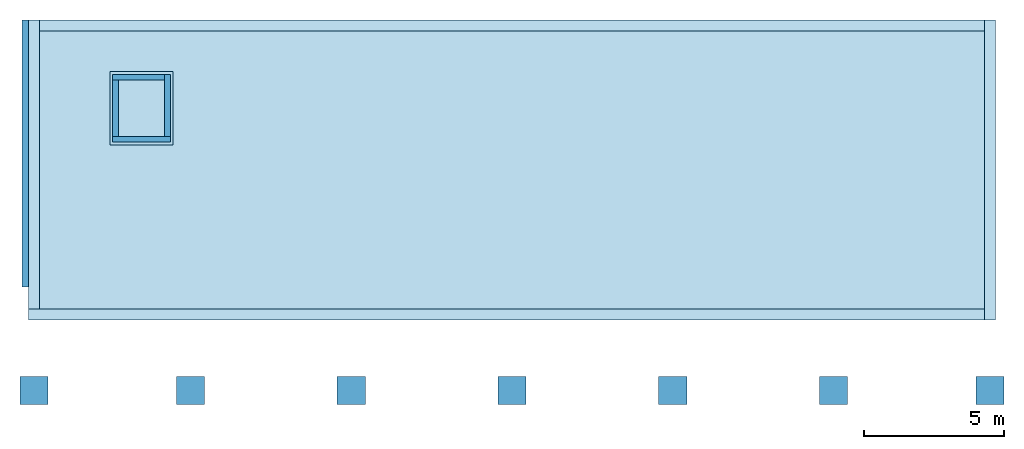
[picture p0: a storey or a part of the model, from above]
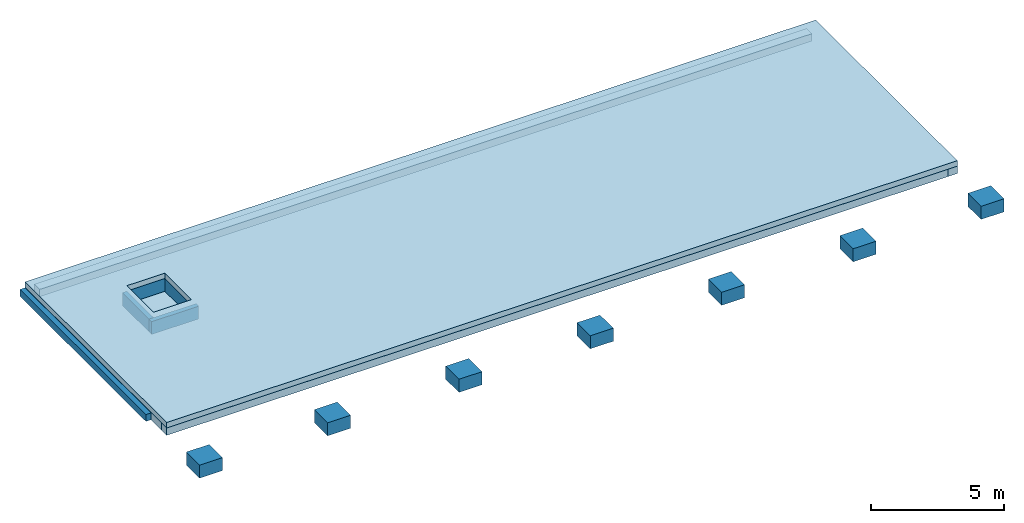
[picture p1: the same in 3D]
Properties of the parts of a building model (IFC4), part 1 of 2

# File
Description: no view
File name: LYC-1518-MDL-DMC-STR-Global.ifc
Time: 2025-12-04T12:50:37
Author: Thibaut
Organization: Adem, bureau d'études, Place de Flandre, 9 - B-7000 Mons
Written by: EDMsix Version 2.0.209.92 Dec 12 2020
Made in: Allplan 2022.1 20.06.2024 - 13:41:00

# IfcSite, Site
RefLatitude: 48, 8, 10, 320000; RefLongitude: 11, 41, 19, 320000

# IfcBuildingStorey (10)
Name | In | Elevation (m)
-01-Fondations | Admin | -0.8
00-Rez | Admin | -0.26
01-Etage1 | Admin | 3.25
02-Etage2 | Admin | 6.61
03-Toiture | Admin | 9.64
-01-Fondations | Auditorium | -0.8
00-Rez | Auditorium | -0.26
01-Toiture | Auditorium | 3.9
-01-Fondations | PosteGarde | -0.02
00-Rez | PosteGarde | 0.88

# IfcSpace (5)
In: 03-Toiture
LongName: Atelier; Classification: 1020 Project Program (Uniformat)
Pset_SpaceCommon - IsExternal: no; HandicapAccessible: yes; GrossPlannedArea: 0 m2; NetPlannedArea: 100 m2; PubliclyAccessible: yes; Reference: AT
Qto_SpaceBaseQuantities - FinishFloorHeight: 0 m
Name | NetFloorArea (m2) | GrossFloorArea (m2) | GrossWallArea (m2) | NetWallArea (m2) | NetPerimeter (m) | GrossVolume (m3) = NetVolume (m3) | FinishCeilingHeight (m)
AT-xx-01 | 17.432 | 17.432 | 4.61 | 1.709 | 18.675 | 4.303 | 0.247
AT-xx-01 | 20.869 | 20.869 | 4.738 | 1.119 | 18.65 | 5.302 | 0.254
2 x AT-xx-01 | 10.202 | 10.202 | 3.285 | 0.547 | 12.93 | 2.592 | 0.254
AT-xx-01 | 0.22 | 294.621 | 43.025 | 29.085 | 152.225 | 83.272 | 0.283

# IfcBeam (143)
Name | In | Classification | Material | Status | LoadBearing | Height (m) | Width (m) | CrossSectionArea (m2) | GrossVolume (m3) | Length (m) | IsExternal | NetVolume (m3) | OuterSurfaceArea (m2)
Linteau préfab. | 00-Rez | B1010 Floor Construction (Uniformat) | C30/37 | NEW | yes | 0.2 | 0.15 | 0.03 | 0.039 | 1.31
PBAr.0.04 | 00-Rez | B2080 Exterior Wall Appurtenances (Uniformat) | Béton architectonique | NEW | no | 1.6 | 0.12 | 0.192 | 6.874 | 35.8 | yes | 6.874 | 123.536
PBAr.0.02 | 00-Rez | B2080 Exterior Wall Appurtenances (Uniformat) | Béton architectonique | NEW | yes | 1.6 | 0.12 | 0.192 | 7.21 | 37.55 | yes | 7.21 | 129.78
PBAr.0.01 | 00-Rez | B2080 Exterior Wall Appurtenances (Uniformat) | Béton architectonique | NEW | yes | 1.6 | 0.12 | 0.192 | 0.691 | 3.6 | yes | 0.691 | 12.768
PBAr.0.03 | 00-Rez | B2080 Exterior Wall Appurtenances (Uniformat) | Béton architectonique | NEW | yes | 1.6 | 0.12 | 0.192 | 2.717 | 14.15 | yes | 2.717 | 49.06
PBA.0.02 | 00-Rez | B1010 Floor Construction (Uniformat) | C30/37 | NEW | yes | 0.07 | 0.16 | 0.011 | 0.013 | 1.13 | yes | 0.013 | 0.542
2 x PBA.0.02 | 00-Rez | B1010 Floor Construction (Uniformat) | C30/37 | NEW | yes | 0.07 | 0.16 | 0.011 | 0.014 | 1.28 | yes | 0.014 | 0.611
PBA.0.02 | 00-Rez | B1010 Floor Construction (Uniformat) | C30/37 | NEW | yes | 1.12 | 0.16 | 0.179 | 1.335 | 7.45 | yes | 1.335 | 19.43
PBA.0.02 | 00-Rez | B1010 Floor Construction (Uniformat) | C30/37 | NEW | yes | 1.12 | 0.16 | 0.179 | 1.821 | 10.16 | yes | 1.821 | 26.368
PBA.0.02 | 00-Rez | B1010 Floor Construction (Uniformat) | C30/37 | NEW | yes | 1.12 | 0.16 | 0.179 | 0.803 | 4.48 | yes | 0.803 | 11.827
PBA.0.02 | 00-Rez | B1010 Floor Construction (Uniformat) | C30/37 | NEW | yes | 1.12 | 0.16 | 0.179 | 0.493 | 2.75 | yes | 0.493 | 7.398
PBA.0.02 | 00-Rez | B1010 Floor Construction (Uniformat) | C30/37 | NEW | yes | 0.07 | 0.16 | 0.011 | 0.014 | 1.24 | yes | 0.014 | 0.593
PBA.0.03 | 00-Rez | B1010 Floor Construction (Uniformat) | C30/37 | NEW | yes | 0.07 | 0.16 | 0.011 | 0.014 | 1.265 | yes | 0.014 | 0.604
PBA.0.03 | 00-Rez | B1010 Floor Construction (Uniformat) | C30/37 | NEW | yes | 1.12 | 0.16 | 0.179 | 0.186 | 1.04 | yes | 0.186 | 3.021
PBA.0.02 | 00-Rez | B1010 Floor Construction (Uniformat) | C30/37 | NEW | yes | 1.12 | 0.16 | 0.179 | 0.74 | 4.13 | yes | 0.74 | 10.931
PBA.0.03 | 00-Rez | B1010 Floor Construction (Uniformat) | C30/37 | NEW | yes | 1.12 | 0.16 | 0.179 | 1.436 | 8.015 | yes | 1.436 | 20.877
PBA.0.02 | 00-Rez | B1010 Floor Construction (Uniformat) | C30/37 | NEW | yes | 0.6 | 0.2 | 0.12 | 4.058 | 33.82 | yes | 4.058 | 54.352
PBA.0.03 | 00-Rez | B1010 Floor Construction (Uniformat) | C30/37 | NEW | yes | 0.6 | 0.2 | 0.12 | 1.234 | 10.28 | yes | 1.234 | 16.688
PBA.0.06 | 00-Rez | B1010 Floor Construction (Uniformat) | C30/37 | NEW | yes | 0.95 | 0.2 | 0.19 | 0.314 | 1.65 | yes | 0.314 | 4.175
PBA.0.07 | 00-Rez | B1010 Floor Construction (Uniformat) | C30/37 | NEW | yes | 0.2 | 0.15 | 0.03 | 0.104 | 3.466 | yes | 0.104 | 2.486
PBA.0.09 | 00-Rez | B1010 Floor Construction (Uniformat) | C30/37 | NEW | yes | 0.08 | 0.214 | 0.017 | 0.055 | 3.22 | yes | 0.055 | 1.928
PBA.0.11 | 00-Rez | B1010 Floor Construction (Uniformat) | C30/37 | NEW | yes | 0.08 | 0.15 | 0.012 | 0.028 | 2.319 | yes | 0.028 | 1.091
PBA.0.10 | 00-Rez | B1010 Floor Construction (Uniformat) | C30/37 | NEW | yes | 0.08 | 0.15 | 0.012 | 0.028 | 2.32 | yes | 0.028 | 1.091
PBA.0.08 | 00-Rez | B1010 Floor Construction (Uniformat) | C30/37 | NEW | yes | 0.08 | 0.214 | 0.017 | 0.024 | 1.4 | yes | 0.024 | 0.857
PBA.0.12 | 00-Rez | B1010 Floor Construction (Uniformat) | C30/37 | NEW | yes | 0.64 | 0.2 | 0.128 | 0.471 | 3.68 | yes | 0.471 | 6.438
PBA.0.01 | 00-Rez | B1010 Floor Construction (Uniformat) | C30/37 | NEW | yes | 1.12 | 0.16 | 0.179 | 0.846 | 4.72 | yes | 0.846 | 12.442
PBA.0.01 | 00-Rez | B1010 Floor Construction (Uniformat) | C30/37 | NEW | yes | 0.6 | 0.2 | 0.12 | 0.566 | 4.72 | yes | 0.566 | 7.792
PBA.0.04 | 00-Rez | B1010 Floor Construction (Uniformat) | C30/37 | NEW | yes | 1.12 | 0.16 | 0.179 | 1.254 | 7 | yes | 1.254 | 18.278
PBA.0.04 | 00-Rez | B1010 Floor Construction (Uniformat) | C30/37 | NEW | yes | 0.6 | 0.2 | 0.12 | 0.84 | 7 | yes | 0.84 | 11.44
PBA.0.05 | 00-Rez | B1010 Floor Construction (Uniformat) | C30/37 | NEW | yes | 0.6 | 0.2 | 0.12 | 1.526 | 12.72 | yes | 1.526 | 20.592
PBA.0.05 | 00-Rez | B1010 Floor Construction (Uniformat) | C30/37 | NEW | yes | 1.12 | 0.16 | 0.179 | 2.279 | 12.72 | yes | 2.279 | 32.922
P 1.05 | 01-Etage1 | B1010 Floor Construction (Uniformat) | GL24h | NEW | yes | 0.52 | 0.2 | 0.104 | 0.477 | 4.59 | yes | 0.477 | 6.818
P 1.04 | 01-Etage1 | B1010 Floor Construction (Uniformat) | GL24h | NEW | yes | 0.52 | 0.2 | 0.104 | 0.477 | 4.59 | yes | 0.477 | 6.818
P 1.03 | 01-Etage1 | B1010 Floor Construction (Uniformat) | GL24h | NEW | yes | 0.52 | 0.2 | 0.104 | 0.477 | 4.59 | yes | 0.477 | 6.818
P 1.14 | 01-Etage1 | B1010 Floor Construction (Uniformat) | GL24h | NEW | yes | 0.4 | 0.2 | 0.08 | 0.262 | 3.27 | yes | 0.262 | 4.084
P 1.13 | 01-Etage1 | B1010 Floor Construction (Uniformat) | GL24h | NEW | yes | 0.4 | 0.2 | 0.08 | 0.262 | 3.27 | yes | 0.262 | 4.084
P 1.15 | 01-Etage1 | B1010 Floor Construction (Uniformat) | GL24h | NEW | yes | 0.4 | 0.2 | 0.08 | 0.262 | 3.27 | yes | 0.262 | 4.084
P 1.12 | 01-Etage1 | B1010 Floor Construction (Uniformat) | GL24h | NEW | yes | 0.4 | 0.2 | 0.08 | 0.262 | 3.27 | yes | 0.262 | 4.084
P 1.10 | 01-Etage1 | B1010 Floor Construction (Uniformat) | GL24h | NEW | yes | 0.4 | 0.2 | 0.08 | 0.262 | 3.27 | yes | 0.262 | 4.084
P 1.11 | 01-Etage1 | B1010 Floor Construction (Uniformat) | GL24h | NEW | yes | 0.4 | 0.2 | 0.08 | 0.262 | 3.27 | yes | 0.262 | 4.084
P 1.09 | 01-Etage1 | B1010 Floor Construction (Uniformat) | GL24h | NEW | yes | 0.4 | 0.2 | 0.08 | 0.262 | 3.27 | yes | 0.262 | 4.084
PM 1.06 | 01-Etage1 | B1010 Floor Construction (Uniformat) | S235 | NEW | yes | 0.09 | 0.18 | 0.003 | 0.005 | 1.5 |  | 0.005 | 0.797
PM 1.07 | 01-Etage1 | B1010 Floor Construction (Uniformat) | S235 | NEW | yes | 0.09 | 0.18 | 0.003 | 0.005 | 1.5 |  | 0.005 | 0.797
PM 1.03 | 01-Etage1 | B1010 Floor Construction (Uniformat) | S235 | NEW | yes | 0.09 | 0.18 | 0.003 | 0.005 | 1.5 |  | 0.005 | 0.797
PM 1.04 | 01-Etage1 | B1010 Floor Construction (Uniformat) | S235 | NEW | yes | 0.09 | 0.18 | 0.003 | 0.005 | 1.5 |  | 0.005 | 0.797
PM 1.05 | 01-Etage1 | B1010 Floor Construction (Uniformat) | S235 | NEW | yes | 0.09 | 0.18 | 0.003 | 0.005 | 1.5 |  | 0.005 | 0.797
P 1.19 | 01-Etage1 | B1010 Floor Construction (Uniformat) | GL24h | NEW | yes | 0.6 | 0.2 | 0.12 | 0.797 | 6.64 | yes | 0.797 | 10.864
P 1.18 | 01-Etage1 | B1010 Floor Construction (Uniformat) | GL24h | NEW | yes | 0.6 | 0.2 | 0.12 | 0.797 | 6.64 | yes | 0.797 | 10.864
PM 1.08 | 01-Etage1 | B1010 Floor Construction (Uniformat) | S235 | NEW | yes | 0.09 | 0.18 | 0.003 | 0.005 | 1.5 |  | 0.005 | 0.797
PM 1.09 | 01-Etage1 | B1010 Floor Construction (Uniformat) | S235 | NEW | yes | 0.09 | 0.18 | 0.003 | 0.005 | 1.5 |  | 0.005 | 0.797
P 1.16 | 01-Etage1 | B1010 Floor Construction (Uniformat) | GL24h | NEW | yes | 0.4 | 0.2 | 0.08 | 0.262 | 3.27 | yes | 0.262 | 4.084
P BA 1.02 | 01-Etage1 | B1010 Floor Construction (Uniformat) | C30/37 | NEW | yes | 0.2 | 0.2 | 0.04 | 0.052 | 1.31 | yes | 0.052 | 1.128
P 1.20 | 01-Etage1 | B1010 Floor Construction (Uniformat) | GL24h | NEW | yes | 0.6 | 0.2 | 0.12 | 0.797 | 6.64 | yes | 0.797 | 10.864
P 1.17 | 01-Etage1 | B1010 Floor Construction (Uniformat) | GL24h | NEW | yes | 0.4 | 0.2 | 0.08 | 0.182 | 2.28 | yes | 0.182 | 2.896
P 1.08 | 01-Etage1 | B1010 Floor Construction (Uniformat) | GL24h | NEW | yes | 0.4 | 0.2 | 0.08 | 0.262 | 3.27 | yes | 0.262 | 4.084
P 1.02 | 01-Etage1 | B1010 Floor Construction (Uniformat) | GL24h | NEW | yes | 0.52 | 0.2 | 0.104 | 0.515 | 4.95 | yes | 0.515 | 7.336
PM 1.02 | 01-Etage1 | B1010 Floor Construction (Uniformat) | S235 | NEW | yes | 0.09 | 0.18 | 0.003 | 0.005 | 1.5 |  | 0.005 | 0.797
PBA 1.01 | 01-Etage1 | B1010 Floor Construction (Uniformat) | C30/37 | NEW | yes | 0.96 | 0.2 | 0.192 | 0.317 | 1.65 | yes | 0.317 | 4.212
PM 1.01 | 01-Etage1 | B1010 Floor Construction (Uniformat) | S235 | NEW | yes | 0.09 | 0.18 | 0.003 | 0.005 | 1.5 |  | 0.005 | 0.797
P 1.01 | 01-Etage1 | B1010 Floor Construction (Uniformat) | GL24h | NEW | yes | 0.24 | 0.2 | 0.048 | 0.079 | 1.64 | yes | 0.079 | 1.539
Poutre CLT Axe 2.2 R+1 | 01-Etage1 | B2010 Exterior Walls (Uniformat) | CLT | NEW | yes | 1.22 | 0.16 | 0.195 | 6.617 | 33.9 |  | 6.617 | 93.954
Poutre CLT Axe 2.M R+1 | 01-Etage1 | B2010 Exterior Walls (Uniformat) | CLT | NEW | yes | 1.22 | 0.16 | 0.195 | 2.046 | 10.48 |  | 2.046 | 29.315
Poutre CLT Axe 2.6 R+1 | 01-Etage1 | B2010 Exterior Walls (Uniformat) | CLT | NEW | yes | 1.22 | 0.16 | 0.195 | 1.335 | 6.84 |  | 1.335 | 19.269
Bandeau R+1 | 01-Etage1 | B1010 Floor Construction (Uniformat) | C30/37 | NEW | yes | 0.76 | 0.2 | 0.152 | 0.029 | 0.19 | yes | 0.029 | 0.669
Poutre CLT Axe 2.A R+1 | 01-Etage1 | B2010 Exterior Walls (Uniformat) | CLT | NEW | yes | 1.22 | 0.16 | 0.195 | 1.04 | 5.33 |  | 1.04 | 15.101
P 1.07 | 01-Etage1 | B1010 Floor Construction (Uniformat) | GL24h | NEW | yes | 0.52 | 0.2 | 0.104 | 0.498 | 4.79 | yes | 0.498 | 7.106
Poutre CLT Axe 2.6 R+1 | 01-Etage1 | B2010 Exterior Walls (Uniformat) | CLT | NEW | yes | 1.22 | 0.16 | 0.195 | 2.483 | 12.72 |  | 2.483 | 35.498
P 1.06 | 01-Etage1 | B1010 Floor Construction (Uniformat) | GL24h | NEW | yes | 0.52 | 0.2 | 0.104 | 0.477 | 4.59 | yes | 0.477 | 6.818
P BA 2.01 | 02-Etage2 | B1020 Roof Construction (Uniformat) | C30/37 | NEW | yes | 0.6 | 0.2 | 0.12 | 0.18 | 1.5 | yes | 0.152 | 3.299
P BA 2.01 | 02-Etage2 | B1020 Roof Construction (Uniformat) | C30/37 | NEW | yes | 1.34 | 0.2 | 0.268 | 0.442 | 1.65 | yes | 0.442 | 5.618
Poutre CLT Axe 2.A R+2 | 02-Etage2 | B2010 Exterior Walls (Uniformat) | CLT | NEW | yes | 0.71 | 0.16 | 0.114 | 0.587 | 5.17 |  | 0.587 | 9.223
Poutre CLT Axe 2.2 R+2 | 02-Etage2 | B2010 Exterior Walls (Uniformat) | CLT | NEW | yes | 0.71 | 0.16 | 0.114 | 3.887 | 34.22 |  | 3.887 | 59.77
Poutre CLT Axe 2.M R+2 | 02-Etage2 | B2010 Exterior Walls (Uniformat) | CLT | NEW | yes | 0.71 | 0.16 | 0.114 | 1.172 | 10.32 |  | 1.172 | 18.184
Poutre CLT Axe 2.6 R+2 | 02-Etage2 | B2010 Exterior Walls (Uniformat) | CLT | NEW | yes | 0.71 | 0.16 | 0.114 | 0.777 | 6.84 |  | 0.777 | 12.129
Poutre CLT Axe 2.6 R+2 | 02-Etage2 | B2010 Exterior Walls (Uniformat) | CLT | NEW | yes | 0.71 | 0.16 | 0.114 | 1.445 | 12.72 |  | 1.445 | 22.36
Poutre CLT Axe 2.2 R+2 | 03-Toiture | B2010 Exterior Walls (Uniformat) | CLT | NEW | yes | 0.202 | 0.16 | 0.032 | 1.103 | 34.06 |  | 1.103 | 24.748
PM 2.08 | 03-Toiture | B1020 Roof Construction (Uniformat) | S235 | NEW | yes | 0.09 | 0.18 | 0.003 | 0.005 | 1.501 |  | 0.005 | -129.703
2 x PM 2.05 | 03-Toiture | B1020 Roof Construction (Uniformat) | S235 | NEW | yes | 0.09 | 0.18 | 0.003 | 0.005 | 1.501 |  | 0.005 | -129.703
PM 2.06 | 03-Toiture | B1020 Roof Construction (Uniformat) | S235 | NEW | yes | 0.09 | 0.18 | 0.003 | 0.005 | 1.501 |  | 0.005 | -129.703
PM 2.07 | 03-Toiture | B1020 Roof Construction (Uniformat) | S235 | NEW | yes | 0.09 | 0.18 | 0.003 | 0.005 | 1.501 |  | 0.005 | -129.703
PM 2.02 | 03-Toiture | B1020 Roof Construction (Uniformat) | S235 | NEW | yes | 0 | 0.18 | 0.003 | 0.005 | 1.5 |  | 0.005 | -129.703
PM 2.04 | 03-Toiture | B1020 Roof Construction (Uniformat) | S235 | NEW | yes | 0.09 | 0.18 | 0.003 | 0.005 | 1.501 |  | 0.005 | -129.703
PM 2.01 | 03-Toiture | B1020 Roof Construction (Uniformat) | S235 | NEW | yes | 0 | 0.18 | 0.003 | 0.005 | 1.5 |  | 0.005 | -129.703
Poutre CLT Axe 2.6 R+2 | 03-Toiture | B2010 Exterior Walls (Uniformat) | CLT | NEW | yes | 0.202 | 0.16 | 0.032 | 0.412 | 12.72 |  | 0.412 | 9.285
Poutre CLT Axe 2.6 R+2 | 03-Toiture | B2010 Exterior Walls (Uniformat) | CLT | NEW | yes | 0.202 | 0.16 | 0.032 | 0.227 | 7 |  | 0.227 | 5.139
Poutre CLT Axe 2.M R+2 | 03-Toiture | B2010 Exterior Walls (Uniformat) | CLT | NEW | yes | 0.28 | 0.16 | 0.045 | 0.455 | 10.16 |  | 0.455 | 8.999
Poutre CLT Axe 2.A R+2 | 03-Toiture | B2010 Exterior Walls (Uniformat) | CLT | NEW | yes | 0.277 | 0.16 | 0.044 | 0.236 | 5.33 |  | 0.236 | 4.75
P 2.07 20/32 | 03-Toiture | B1020 Roof Construction (Uniformat) | GL24h | NEW | yes | 0.32 | 0.2 | 0.064 | 0.209 | 3.271 |  | 0.209 | 3.53
P 2.08 20/32 | 03-Toiture | B1020 Roof Construction (Uniformat) | GL24h | NEW | yes | 0.32 | 0.2 | 0.064 | 0.209 | 3.271 |  | 0.209 | 3.53
P 2.10 20/32 | 03-Toiture | B1020 Roof Construction (Uniformat) | GL24h | NEW | yes | 0.32 | 0.2 | 0.064 | 0.209 | 3.271 |  | 0.209 | 3.53
P 2.11 20/32 | 03-Toiture | B1020 Roof Construction (Uniformat) | GL24h | NEW | yes | 0.32 | 0.2 | 0.064 | 0.209 | 3.271 |  | 0.209 | 3.53
P 2.12 20/32 | 03-Toiture | B1020 Roof Construction (Uniformat) | GL24h | NEW | yes | 0.32 | 0.2 | 0.064 | 0.209 | 3.271 |  | 0.209 | 3.53
P 2.13 20/32 | 03-Toiture | B1020 Roof Construction (Uniformat) | GL24h | NEW | yes | 0.32 | 0.2 | 0.064 | 0.209 | 3.271 |  | 0.209 | 3.53
P 2.14 20/32 | 03-Toiture | B1020 Roof Construction (Uniformat) | GL24h | NEW | yes | 0.32 | 0.2 | 0.064 | 0.209 | 3.271 |  | 0.209 | 3.53
P 2.15 20/32 | 03-Toiture | B1020 Roof Construction (Uniformat) | GL24h | NEW | yes | 0.32 | 0.2 | 0.064 | 0.209 | 3.271 |  | 0.209 | 3.53
P 2.16 20/56 | 03-Toiture | B1020 Roof Construction (Uniformat) | GL24h | NEW | yes | 0.56 | 0.2 | 0.112 | 0.389 | 3.471 |  | 0.389 | 5.501
P 2.19 20/56 | 03-Toiture | B1020 Roof Construction (Uniformat) | GL24h | NEW | yes | 0.56 | 0.2 | 0.112 | 0.744 | 6.64 |  | 0.744 | 10.321
P 2.18 20/56 | 03-Toiture | B1020 Roof Construction (Uniformat) | GL24h | NEW | yes | 0.56 | 0.2 | 0.112 | 0.744 | 6.64 |  | 0.744 | 10.321
P 2.17 20/56 | 03-Toiture | B1020 Roof Construction (Uniformat) | GL24h | NEW | yes | 0.56 | 0.2 | 0.112 | 0.744 | 6.64 |  | 0.744 | 10.321
P 2.06 20/44 | 03-Toiture | B1020 Roof Construction (Uniformat) | GL24h | NEW | yes | 0.44 | 0.2 | 0.088 | 0.422 | 4.792 |  | 0.422 | 6.31
P 2.05 20/44 | 03-Toiture | B1020 Roof Construction (Uniformat) | GL24h | NEW | yes | 0.44 | 0.2 | 0.088 | 0.404 | 4.592 |  | 0.404 | 6.054
P 2.04 20/44 | 03-Toiture | B1020 Roof Construction (Uniformat) | GL24h | NEW | yes | 0.44 | 0.2 | 0.088 | 0.404 | 4.592 |  | 0.404 | 6.054
P 2.03 20/44 | 03-Toiture | B1020 Roof Construction (Uniformat) | GL24h | NEW | yes | 0.44 | 0.2 | 0.088 | 0.404 | 4.592 |  | 0.404 | 6.054
P 2.02 20/44 | 03-Toiture | B1020 Roof Construction (Uniformat) | GL24h | NEW | yes | 0.44 | 0.2 | 0.088 | 0.404 | 4.592 |  | 0.404 | 6.054
P 2.01 20/44 | 03-Toiture | B1020 Roof Construction (Uniformat) | GL24h | NEW | yes | 0.44 | 0.2 | 0.088 | 0.422 | 4.792 |  | 0.422 | 6.31
PM 2.03 | 03-Toiture | B1020 Roof Construction (Uniformat) | S235 | NEW | yes | 0.09 | 0.18 | 0.003 | 0.005 | 1.501 |  | 0.005 | -129.703
P BA 2.01 | 03-Toiture | B1020 Roof Construction (Uniformat) | C30/37 | NEW | yes | 0.333 | 0.2 | 0.067 | 0.1 | 1.5 | yes | 0.1 | 1.732
P 2.09 20/32 | 03-Toiture | B1020 Roof Construction (Uniformat) | GL24h | NEW | yes | 0.32 | 0.2 | 0.064 | 0.209 | 3.271 |  | 0.209 | 3.53
2 x  | 00-Rez | C1010 Interior Partitions (Uniformat) | Béton préfabriqué | NEW |  | 0.2 | 0.15 | 0.03 | 0.042 | 1.4
2 x Poutre Béton Archi. Audit. | 00-Rez | B2080 Exterior Wall Appurtenances (Uniformat) | Béton architectonique | NEW | no | 1.55 | 0.12 | 0.186 | 0.102 | 0.55 | yes | 0.102 | 2.209
Poutre Béton Archi. Audit. | 00-Rez | B2080 Exterior Wall Appurtenances (Uniformat) | Béton architectonique | NEW | no | 2.9 | 0.12 | 0.348 | 4.628 | 13.3 | yes | 4.628 | 81.028
Poutre Béton Archi. Audit. | 00-Rez | B2080 Exterior Wall Appurtenances (Uniformat) | Béton architectonique | NEW | no | 2.9 | 0.12 | 0.348 | 8.321 | 23.91 | yes | 8.321 | 145.112
Poutre Béton Archi. Audit. | 00-Rez | B2080 Exterior Wall Appurtenances (Uniformat) | Béton architectonique | NEW | no | 2.9 | 0.12 | 0.348 | 7.517 | 21.6 | yes | 7.517 | 131.16
Poutre Béton Archi. Audit. | 00-Rez | B2080 Exterior Wall Appurtenances (Uniformat) | Béton architectonique | NEW | no | 1.6 | 0.1 | 0.16 | 0.453 | 2.83 | yes | 0.453 | 9.942
Poutre Béton Archi. Audit. | 00-Rez | B2080 Exterior Wall Appurtenances (Uniformat) | Béton architectonique | NEW | no | 1.6 | 0.12 | 0.192 | 0.568 | 2.96 | yes | 0.568 | 10.567
Poutre Béton Archi. Audit. | 00-Rez | B2080 Exterior Wall Appurtenances (Uniformat) | Béton architectonique | NEW | no | 2.9 | 0.12 | 0.348 | 0.338 | 0.97 | yes | 0.338 | 6.555
Poutre Béton Archi. Audit. | 00-Rez | B2080 Exterior Wall Appurtenances (Uniformat) | Béton architectonique | NEW | no | 2.9 | 0.12 | 0.348 | 7.475 | 21.48 | yes | 7.475 | 130.435
Poutre Béton Archi. Audit. | 00-Rez | B2080 Exterior Wall Appurtenances (Uniformat) | Béton architectonique | NEW | no | 2.17 | 0.12 | 0.26 | 2.255 | 8.66 | yes | 2.255 | 40.184
2 x  | 00-Rez | C1010 Interior Partitions (Uniformat) | Béton préfabriqué | NEW |  | 0.2 | 0.19 | 0.038 | 0.074 | 1.95
 | 00-Rez | C1010 Interior Partitions (Uniformat) | Béton préfabriqué | NEW |  | 0.2 | 0.19 | 0.038 | 0.053 | 1.4
PBA.0.04 | 00-Rez | B1010 Floor Construction (Uniformat) | C30/37 | NEW | yes | 0.24 | 0.15 | 0.036 | 0.166 | 4.6 | yes | 0.166 | 3.66
PBA.0.03 | 00-Rez | B1010 Floor Construction (Uniformat) | C30/37 | NEW | yes | 0.24 | 0.15 | 0.036 | 0.104 | 2.877 | yes | 0.104 | 2.317
PBA.0.02 | 00-Rez | B1010 Floor Construction (Uniformat) | C30/37 | NEW | yes | 0.24 | 0.15 | 0.036 | 0.287 | 7.97 | yes | 0.287 | 6.289
PBA.0.01 | 00-Rez | B1010 Floor Construction (Uniformat) | C30/37 | NEW | yes | 0.24 | 0.15 | 0.036 | 0.104 | 2.877 | yes | 0.104 | 2.317
PBA.0.05 | 00-Rez | B1010 Floor Construction (Uniformat) | C30/37 | NEW | yes | 0.24 | 0.15 | 0.036 | 0.166 | 4.6 | yes | 0.166 | 3.66
8 x Dalles TT | 01-Toiture | B1020 Roof Construction (Uniformat) | Béton préfabriqué |  | yes |  |  |  | 7.379
Dalles TT | 01-Toiture | B1020 Roof Construction (Uniformat) | Béton préfabriqué |  | yes |  |  |  | 3.745
Poutres Béton archi. PosteGarde | 00-Rez | B2080 Exterior Wall Appurtenances (Uniformat) | Béton architectonique | NEW | yes | 0.75 | 0.15 | 0.113 | 0.596 | 5.3 | yes | 0.596 | 9.765
Poutres Béton archi. PosteGarde | 00-Rez | B2080 Exterior Wall Appurtenances (Uniformat) | Béton architectonique | NEW | yes | 0.75 | 0.15 | 0.112 | 0.686 | 6.1 | yes | 0.686 | 11.205
Poutres Béton archi. PosteGarde | 00-Rez | B2080 Exterior Wall Appurtenances (Uniformat) | Béton architectonique | NEW | yes | 0.75 | 0.15 | 0.112 | 0.579 | 5.15 | yes | 0.579 | 9.495
Poutres Béton archi. PosteGarde | 00-Rez | B2080 Exterior Wall Appurtenances (Uniformat) | Béton architectonique | NEW | yes | 0.75 | 0.15 | 0.112 | 0.669 | 5.95 | yes | 0.669 | 10.935

# IfcColumn (145)
Pset_ColumnCommon - LoadBearing: yes
Name | In | Classification | Material | GrossVolume (m3) | PredefinedType | Status | IsExternal | Width (m) | Depth (m) | CrossSectionArea (m2) | NetVolume (m3) | Length (m) | OuterSurfaceArea (m2)
Totem Admin. | 00-Rez | B1010 Floor Construction (Uniformat) | Béton architectonique | 2.264
CBM.0.04 | 00-Rez | B1010 Floor Construction (Uniformat) | S235 | 0.018 | COLUMN | NEW | yes | 0.194 | 0.03 | 0.006 | 0.018 | 3 | 3.426
CBM.0.01 | 00-Rez | B1010 Floor Construction (Uniformat) | S235 | 0.018 | COLUMN | NEW | yes | 0.194 | 0.03 | 0.006 | 0.018 | 3 | 3.426
CBM.0.06 | 00-Rez | B1010 Floor Construction (Uniformat) | S235 | 0.018 | COLUMN | NEW | yes | 0.194 | 0.03 | 0.006 | 0.018 | 3 | 3.426
CBM.0.05 | 00-Rez | B1010 Floor Construction (Uniformat) | S235 | 0.018 | COLUMN | NEW | yes | 0.194 | 0.03 | 0.006 | 0.018 | 3 | 3.426
CBM.0.03 | 00-Rez | B1010 Floor Construction (Uniformat) | S235 | 0.018 | COLUMN | NEW | yes | 0.194 | 0.03 | 0.006 | 0.018 | 3 | 3.426
CBM.0.02 | 00-Rez | B1010 Floor Construction (Uniformat) | S235 | 0.018 | COLUMN | NEW | yes | 0.194 | 0.03 | 0.006 | 0.018 | 3 | 3.426
CBA.0.04 | 00-Rez | B1010 Floor Construction (Uniformat) | C30/37 | 0.091 | COLUMN | NEW | yes | 0 | 0 | 0.031 | 0.091 | 2.91 | 1.837
CBA.0.05 | 00-Rez | B1010 Floor Construction (Uniformat) | C30/37 | 0.091 | COLUMN | NEW | yes | 0 | 0 | 0.031 | 0.091 | 2.91 | 1.837
CBA.0.03 | 00-Rez | B1010 Floor Construction (Uniformat) | C30/37 | 0.091 | COLUMN | NEW | yes | 0 | 0 | 0.031 | 0.091 | 2.91 | 1.837
CBA.0.02 | 00-Rez | B1010 Floor Construction (Uniformat) | C30/37 | 0.091 | COLUMN | NEW | yes | 0 | 0 | 0.031 | 0.091 | 2.91 | 1.837
CBA.0.01 | 00-Rez | B1010 Floor Construction (Uniformat) | C30/37 | 0.091 | COLUMN | NEW | yes | 0 | 0 | 0.031 | 0.091 | 2.91 | 1.837
CBA.0.06 | 00-Rez | B1010 Floor Construction (Uniformat) | C30/37 | 0.091 | COLUMN | NEW | yes | 0 | 0 | 0.031 | 0.091 | 2.91 | 1.837
CBA.0.11 | 00-Rez | B1010 Floor Construction (Uniformat) | C30/37 | 0.091 | COLUMN | NEW | yes | 0 | 0 | 0.031 | 0.091 | 2.91 | 1.837
CBA.0.08 | 00-Rez | B1010 Floor Construction (Uniformat) | C30/37 | 0.091 | COLUMN | NEW | yes | 0 | 0 | 0.031 | 0.091 | 2.91 | 1.837
CBA.0.07 | 00-Rez | B1010 Floor Construction (Uniformat) | C30/37 | 0.091 | COLUMN | NEW | yes | 0 | 0 | 0.031 | 0.091 | 2.91 | 1.837
CBA.0.13 | 00-Rez | B1010 Floor Construction (Uniformat) | C30/37 | 0.091 | COLUMN | NEW | yes | 0 | 0 | 0.031 | 0.091 | 2.91 | 1.837
CBA.0.12 | 00-Rez | B1010 Floor Construction (Uniformat) | C30/37 | 0.091 | COLUMN | NEW | yes | 0 | 0 | 0.031 | 0.091 | 2.91 | 1.837
CBA.0.15 | 00-Rez | B1010 Floor Construction (Uniformat) | C30/37 | 0.287 | COLUMN | NEW | yes | 0.4 | 0.22 | 0.088 | 0.287 | 3.26 | 4.042
CBA.0.10 | 00-Rez | B1010 Floor Construction (Uniformat) | C30/37 | 0.087 | COLUMN | NEW | yes | 0.2 | 0.15 | 0.03 | 0.087 | 2.91 | 2.037
CBA.0.09 | 00-Rez | B1010 Floor Construction (Uniformat) | C30/37 | 0.087 | COLUMN | NEW | yes | 0.2 | 0.15 | 0.03 | 0.087 | 2.91 | 2.037
CBA.0.14 | 00-Rez | B1010 Floor Construction (Uniformat) | C30/37 | 0.087 | COLUMN | NEW | yes | 0.2 | 0.15 | 0.03 | 0.087 | 2.91 | 2.037
CBA.0.16 | 00-Rez | B1010 Floor Construction (Uniformat) | C30/37 | 0.282 | COLUMN | NEW | yes | 0.4 | 0.22 | 0.088 | 0.282 | 3.21 | 3.98
40 x Colonnes bois R+1 | 01-Etage1 | B1010 Floor Construction (Uniformat) | GL24h | 0.134 | COLUMN | NEW | yes | 0.2 | 0.2 | 0.04 | 0.134 | 3.36 | 2.688
C BA 2.01 | 02-Etage2 | B1020 Roof Construction (Uniformat) | C30/37 | 0.115 | COLUMN | NEW | yes | 0.2 | 0.2 | 0.04 | 0.115 | 2.87 | 2.296
36 x Colonne bois R+2 | 02-Etage2 | B1020 Roof Construction (Uniformat) | GL24h | 0.115 | COLUMN | NEW | yes | 0.2 | 0.2 | 0.04 | 0.115 | 2.87 | 2.296
3 x Colonne bois R+2 | 02-Etage2 | B1020 Roof Construction (Uniformat) | GL24h | 0.114 | COLUMN | NEW | yes | 0.2 | 0.2 | 0.04 | 0.114 | 2.854 | 2.283
10 x Colonnes bois R+2 | 03-Toiture | B1020 Roof Construction (Uniformat) | GL24h | 0.012 | COLUMN | NEW | yes | 0.2 | 0.2 | 0.04 | 0.012 | 0.308 | 0.247
7 x Colonnes bois R+2 | 03-Toiture | B1020 Roof Construction (Uniformat) | GL24h | 0.014 | COLUMN | NEW | yes | 0.2 | 0.2 | 0.04 | 0.014 | 0.352 | 0.281
20 x Colonnes bois R+2 | 03-Toiture | B1020 Roof Construction (Uniformat) | GL24h | 0.008 | COLUMN | NEW | yes | 0.2 | 0.2 | 0.04 | 0.008 | 0.208 | 0.166
Colonnes bois R+2 | 03-Toiture | B1020 Roof Construction (Uniformat) | GL24h | 0.011 | COLUMN | NEW | yes | 0.2 | 0.2 | 0.04 | 0.011 | 0.274 | 0.219
Colonnes bois R+2 | 03-Toiture | B1020 Roof Construction (Uniformat) | GL24h | 0.011 | COLUMN | NEW | yes | 0.2 | 0.2 | 0.04 | 0.011 | 0.276 | 0.221
C BA 2.01 | 03-Toiture | B1020 Roof Construction (Uniformat) | C30/37 | 0.012 | COLUMN | NEW | yes | 0.2 | 0.2 | 0.04 | 0.012 | 0.308 | 0.247
2 x Totem Audit. | 00-Rez | B1020 Roof Construction (Uniformat) | Béton architectonique | 2.595

# IfcFooting (39)
In: -01-Fondations
Classification: A1010 Standard Foundations (Uniformat); Material: C30/37
Pset_FootingCommon - Status: NEW; LoadBearing: yes
Name | PredefinedType | Length (m) | NetVolume (m3) | Width (m) | OuterSurfaceArea (m2) | Height (m) | GrossVolume (m3)
Axe 2.A | STRIP_FOOTING | 10.28 | 1.398 | 0.4 | 4.112 | 0.34 | 1.398
Axe 2.A | STRIP_FOOTING | 9.5 | 0.669 | 0.22 | 2.09 | 0.32 | 0.669
Axe 2.M | STRIP_FOOTING | 10.68 | 1.452 | 0.4 | 4.272 | 0.34 | 1.452
Axe 2.2 | STRIP_FOOTING | 34.02 | 4.627 | 0.4 | 13.608 | 0.34 | 4.627
SP.02 | PAD_FOOTING | 1 | 0.6 | 1 | 1 | 0.6 | 0.6
SP.01 | PAD_FOOTING | 1 | 0.6 | 1 | 1 | 0.6 | 0.6
SP.07 | PAD_FOOTING | 1 | 0.6 | 1 | 1 | 0.6 | 0.6
SP.06 | PAD_FOOTING | 1 | 0.6 | 1 | 1 | 0.6 | 0.6
SP.04 | PAD_FOOTING | 1 | 0.6 | 1 | 1 | 0.6 | 0.6
SP.03 | PAD_FOOTING | 1 | 0.6 | 1 | 1 | 0.6 | 0.6
SP.05 | PAD_FOOTING | 1 | 0.6 | 1 | 1 | 0.6 | 0.6
Axe 2.6 | STRIP_FOOTING | 33.62 | 4.572 | 0.4 | 13.448 | 0.34 | 4.572
Axe 1.1 | STRIP_FOOTING | 15.076 | 2.261 | 0.25 | 3.769 | 0.6 | 2.261
Oblique Axe 1.A | STRIP_FOOTING | 2.498 | 0.21 | 0.25 | 0.625 | 0.34 | 0.212
Axe 1.6 | STRIP_FOOTING | 2.69 | 0.412 | 0.45 | 1.211 | 0.34 | 0.412
Axe 1.3 | STRIP_FOOTING | 2.69 | 0.366 | 0.4 | 1.076 | 0.34 | 0.366
Oblique Axe 1.D | STRIP_FOOTING | 2.47 | 0.371 | 0.25 | 0.618 | 0.6 | 0.371
Axe 1.1 | STRIP_FOOTING | 15.26 | 3.434 | 0.3 | 4.578 | 0.75 | 3.434
Oblique Axe 1.A | STRIP_FOOTING | 0.307 | 0.172 | 1 | 0.307 | 0.56 | 0.172
Oblique Axe 1.D | STRIP_FOOTING | 0.307 | 0.092 | 1 | 0.307 | 0.3 | 0.092
Axe 1.2 | STRIP_FOOTING | 3.865 | 3.865 | 1 | 3.865 | 1 | 3.865
Axe 1.2 | STRIP_FOOTING | 3.785 | 3.785 | 1 | 3.785 | 1 | 3.785
Oblique Axe 1.A | STRIP_FOOTING | 13.755 | 2.022 | 0.3 | 4.127 | 0.49 | 2.022
Oblique Axe 1.A | STRIP_FOOTING | 9.728 | 0.827 | 0.25 | 2.432 | 0.34 | 0.827
Axe 1.D | STRIP_FOOTING | 0.057 | 0.013 | 0.3 | 0.017 | 0.75 | 0.013
Axe 1.D | STRIP_FOOTING | 0.736 | 0.108 | 0.3 | 0.221 | 0.49 | 0.108
Oblique Axe 1.D | STRIP_FOOTING | 9.728 | 1.459 | 0.25 | 2.432 | 0.6 | 1.459
Oblique Axe 1.D | STRIP_FOOTING | 13.448 | 3.026 | 0.3 | 4.034 | 0.75 | 3.026
Axe 1.7 | STRIP_FOOTING | 21.5 | 3.16 | 0.3 | 6.45 | 0.49 | 3.16
Axe 1.7 | STRIP_FOOTING | 20.65 | 1.755 | 0.25 | 5.162 | 0.34 | 1.755
Axe 1.2 | STRIP_FOOTING | 16.434 | 18.899 | 1 | 16.434 | 1.15 | 18.899
Axe 1.A | STRIP_FOOTING | 10.333 | 1.519 | 0.3 | 3.1 | 0.49 | 1.519
Axe 1.D | STRIP_FOOTING | 9.54 | 0.916 | 0.3 | 2.862 | 0.32 | 0.916
Axe 1.A | STRIP_FOOTING | 10.302 | 0.876 | 0.25 | 2.576 | 0.34 | 0.876
Axe 1.D | STRIP_FOOTING | 10.052 | 0.854 | 0.25 | 2.513 | 0.34 | 0.854
2 x Bêche PosteGarde | STRIP_FOOTING | 3.6 | 1.17 | 0.5 | 1.8 | 0.65 | 1.17
2 x Bêche PosteGarde | STRIP_FOOTING | 5.4 | 1.755 | 0.5 | 2.7 | 0.65 | 1.755

# IfcGeographicElement (4)
PredefinedType: USERDEFINED; Classification: 1040 Existing Conditions (Uniformat)
Name | In
GlobalLambert72Ref | Site
Ref-Admin | Admin
RefAuditorium | Auditorium
RefGarde | PosteGarde

# IfcMember (264)
Classification: B2080 Exterior Wall Appurtenances (Uniformat)
Pset_MemberCommon - Status: NEW; LoadBearing: yes
Name | In | Material | CrossSectionArea (m2) | GrossVolume (m3) = NetVolume (m3) | Length (m) | OuterSurfaceArea (m2)
2 x Colonnes bois R+1 | 01-Etage1 | S235 | 0.002 | 0.002 | 0.1 | 0.69
38 x Bandeau R+1 | 01-Etage1 | S235 | 0.002 | 0.002 | 0.1 | 0.69
2 x Bandeau R+1 | 01-Etage1 | C24 | 0.008 | 0.302 | 35.92 | 14.385 | Pset_MemberCommon - IsExternal: yes
4 x Bandeau R+1 | 01-Etage1 | C24 | 0.009 | 0.323 | 35.92 | 15.104 | Pset_MemberCommon - IsExternal: yes
26 x Bandeau R+1 | 01-Etage1 | S235 | 0.002 | 0 | 0.15 | 0.115
54 x Bandeau R+1 | 01-Etage1 | S235 | 0.002 | 0.001 | 0.75 | 0.558
4 x Bandeau R+1 | 01-Etage1 | C24 | 0.009 | 0.105 | 11.7 | 4.932 | Pset_MemberCommon - IsExternal: yes
2 x Bandeau R+1 | 01-Etage1 | C24 | 0.008 | 0.098 | 11.7 | 4.697 | Pset_MemberCommon - IsExternal: yes
40 x Bandeau R+2 | 02-Etage2 | S235 | 0.002 | 0.002 | 0.1 | 0.69
54 x Bandeau R+2 | 02-Etage2 | S235 | 0.002 | 0.001 | 0.75 | 0.558
26 x Bandeau R+2 | 02-Etage2 | S235 | 0.002 | 0 | 0.15 | 0.115
6 x Bandeau R+2 | 02-Etage2 | C24 | 0.009 | 0.323 | 35.92 | 15.104 | Pset_MemberCommon - IsExternal: yes
6 x Bandeau R+2 | 02-Etage2 | C24 | 0.009 | 0.105 | 11.7 | 4.932 | Pset_MemberCommon - IsExternal: yes

# IfcOpeningElement: Opening (53)
Pset_OpeningElementCommon - Status: NEW
Name | In | Area (m2) | Depth (m) | Volume (m3) | Height (m) | Width (m)
2 x Baie de fenêtre | 00-Rez | 1.65 | 0.2 | 0.33 | 0.75 | 2.2
Baie de porte | 00-Rez | 3.57 | 0.2 | 0.714 | 2.38 | 1.5
Baie de porte | 00-Rez | 2.404 | 0.15 | 0.361 | 2.38 | 1.01
2 x Percement dans mur | 00-Rez | 0.729 | 0.15 | 0.109 | 0.47 | 1.55
Percement dans mur | 00-Rez | 1.175 | 0.214 | 0.251 | 0.47 | 2.5
2 x Baie de fenêtre | 01-Etage1 | 1.54 | 0.2 | 0.308 | 0.7 | 2.2
2 x Niche dans mur | 02-Etage2 | 0.071 | 0.2 | 0.014 | 0.3 | 0.3
2 x Baie de fenêtre | 02-Etage2 | 1.54 | 0.2 | 0.308 | 0.7 | 2.2
3 x Trémie dans dalle | 03-Toiture | 1 | 1 | 0.16 | 0.16 | 1
Trémie dans dalle | 03-Toiture | 1.014 | 1.014 | 0.162 | 0.16 | 1
Baie de fenêtre | 00-Rez | 1.61 | 0.25 | 0.402 | 0.7 | 2.3
Baie de fenêtre | 00-Rez | 1.61 | 0.25 | 0.403 | 0.7 | 2.3
3 x Niche dans mur | 00-Rez | 0.3 | 0.2 | 0.06 | 0.3 | 1
6 x Niche dans mur | 00-Rez | 0.3 | 0.15 | 0.045 | 0.3 | 1
Baie de porte | 00-Rez | 4.068 | 0.2 | 0.814 | 2.26 | 1.8
Baie de porte | 00-Rez | 2.23 | 0.15 | 0.334 | 2.23 | 1
Baie de porte | 00-Rez | 3.503 | 0.2 | 0.701 | 2.26 | 1.55
Baie de porte | 00-Rez | 4.085 | 0.25 | 1.021 | 2.15 | 1.9
Baie de porte | 00-Rez | 6.05 | 0.25 | 1.513 | 2.75 | 2.2
Baie de porte | 00-Rez | 5.635 | 0.25 | 1.409 | 2.45 | 2.3
Baie de porte | 00-Rez | 6.297 | 0.25 | 1.574 | 2.45 | 2.57
Baie de porte | 00-Rez | 4.276 | 0.25 | 1.069 | 2.87 | 1.49
Baie de porte | 00-Rez | 4.338 | 0.2 | 0.868 | 2.41 | 1.8
Baie de fenêtre | 00-Rez | 20.61 | 0.25 | 5.153 | 2.047 | 10.07
Baie de porte | 00-Rez | 2.1 | 0.15 | 0.315 | 2.1 | 1
6 x Niche dans mur | 00-Rez | 0.36 | 0.15 | 0.054 | 0.3 | 1.2
Baie de fenêtre | 00-Rez | 15.505 | 0.25 | 3.876 | 1.538 | 10.078
2 x Baie de porte | 00-Rez | 3.856 | 0.19 | 0.733 | 2.41 | 1.6
Baie de porte | 00-Rez | 2.45 | 0.19 | 0.465 | 2.45 | 1
Trémie dans dalle | 01-Toiture | 0.32 | 0.8 | 0.07 | 0.22 | 0.4 | Pset_OpeningElementCommon - FireExit: no; ProtectedOpening: yes
Trémie dans dalle | 01-Toiture | 1.5 | 1 | 0.33 | 0.22 | 1.5
Baie de porte | 00-Rez | 2.14 | 0.2 | 0.428 | 2.14 | 1 | Pset_OpeningElementCommon - FireExit: no; ProtectedOpening: yes
Baie de fenêtre | 00-Rez | 3.159 | 0.2 | 0.632 | 1.35 | 2.34

# IfcRamp (3)
In: 00-Rez
Classification: B1010 Floor Construction (Uniformat); Material: C30/37

# IfcSlab (85)
Pset_SlabCommon - Status: NEW; LoadBearing: yes
Name | In | PredefinedType | Classification | Material | Length (m) | NetVolume (m3) | Depth (m) | GrossArea (m2) | Width (m) | GrossVolume (m3) | Perimeter (m) | NetArea (m2) | IsExternal
Radier Admin | -01-Fondations | BASESLAB | A4020 Structural Slabs-on-Grade (Uniformat) | C30/37 | 10.584 | 91.072 | 34.42 | 364.289 | 0.25 | 91.072 | 97.52 | 364.289
Dalle fosse | -01-Fondations | FLOOR | A4020 Structural Slabs-on-Grade (Uniformat) | C30/37 | 2.25 | 1.174 | 2.61 | 5.872 | 0.2 | 1.174 | 9.72 | 5.872 | yes
Balcon | 00-Rez | FLOOR | B1010 Floor Construction (Uniformat) | C30/37 | 3.401 | 38.093 | 37.34 | 126.977 | 0.3 | 38.093 | 103.8 | 126.976
Dalle Admin. 25 cm | 00-Rez | FLOOR | B1010 Floor Construction (Uniformat) | C30/37 | 33.82 | 52.611 | 6.222 | 210.444 | 0.25 | 52.611 | 118.14 | 210.443
Dalle Admin. 30 cm | 00-Rez | FLOOR | B1010 Floor Construction (Uniformat) | C30/37 | 15.874 | 30.346 | 6.372 | 101.154 | 0.3 | 30.346 | 53.748 | 101.153
7 x CLT ép. 16 cm | 01-Etage1 | FLOOR | B1010 Floor Construction (Uniformat) | CLT | 2.66 | 1.562 | 3.67 | 9.762 | 0.16 | 1.562 | 12.66 | 9.762 | yes
4 x CLT ép. 16 cm | 01-Etage1 | FLOOR | B1010 Floor Construction (Uniformat) | CLT | 4.99 | 2.124 | 2.66 | 13.273 | 0.16 | 2.124 | 15.3 | 13.273 | yes
8 x CLT ép. 16 cm | 01-Etage1 | FLOOR | B1010 Floor Construction (Uniformat) | CLT | 2.82 | 0.661 | 1.5 | 4.23 | 0.16 | 0.677 | 8.64 | 4.23 | yes
CLT ép. 16 cm | 01-Etage1 | FLOOR | B1010 Floor Construction (Uniformat) | CLT | 6.84 | 2.736 | 2.5 | 17.1 | 0.16 | 2.736 | 18.68 | 17.1 | yes
CLT ép. 16 cm | 01-Etage1 | FLOOR | B1010 Floor Construction (Uniformat) | CLT | 2.5 | 2.736 | 6.84 | 17.1 | 0.16 | 2.736 | 18.68 | 17.1 | yes
CLT ép. 16 cm | 01-Etage1 | FLOOR | B1010 Floor Construction (Uniformat) | CLT | 5.268 | 1.029 | 1.23 | 6.479 | 0.16 | 1.037 | 12.96 | 6.479 | yes
CLT ép. 16 cm | 01-Etage1 | FLOOR | B1010 Floor Construction (Uniformat) | CLT | 6.84 | 2.476 | 2.262 | 15.475 | 0.16 | 2.476 | 19.04 | 15.475 | yes
CLT ép. 16 cm | 01-Etage1 | FLOOR | B1010 Floor Construction (Uniformat) | CLT | 3.67 | 1.485 | 2.528 | 9.278 | 0.16 | 1.485 | 12.44 | 9.279 | yes
CLT ép. 16 cm | 01-Etage1 | FLOOR | B1010 Floor Construction (Uniformat) | CLT | 3.67 | 1.562 | 2.66 | 9.762 | 0.16 | 1.562 | 12.66 | 9.762 | yes
CLT ép. 16 cm | 01-Etage1 | FLOOR | B1010 Floor Construction (Uniformat) | CLT | 4.979 | 2.772 | 3.48 | 17.325 | 0.16 | 2.772 | 17.34 | 17.325 | yes
Dalle BA R+1 | 01-Etage1 | FLOOR | B1010 Floor Construction (Uniformat) | C30/37 | 0.9 | 0.238 | 1.65 | 1.485 | 0.16 | 0.238 | 5.1 | 1.485
Escalier Préfab. | 01-Etage1 | FLOOR | B1010 Floor Construction (Uniformat) | C30/37 | 2.66 | 0.779 | 1.829 | 4.866 | 0.16 | 0.779 | 8.979 | 4.866
Escalier Préfab. | 01-Etage1 | FLOOR | B1010 Floor Construction (Uniformat) | C30/37 | 2.7 | 0.791 | 1.83 | 4.941 | 0.16 | 0.791 | 9.06 | 4.941
CLT ép. 16 cm | 01-Etage1 | FLOOR | B1010 Floor Construction (Uniformat) | CLT | 1.5 | 0.623 | 2.63 | 3.945 | 0.16 | 0.631 | 8.26 | 3.945 | yes
CLT ép. 16 cm | 01-Etage1 | FLOOR | B1010 Floor Construction (Uniformat) | CLT | 1.23 | 0.982 | 4.99 | 6.138 | 0.16 | 0.982 | 12.44 | 6.138 | yes
CLT ép. 16 cm | 01-Etage1 | FLOOR | B1010 Floor Construction (Uniformat) | CLT | 4.777 | 2.033 | 2.66 | 12.706 | 0.16 | 2.033 | 16.38 | 12.707 | yes
Dalle BA | 02-Etage2 | FLOOR | B1020 Roof Construction (Uniformat) | C30/37 | 2.41 | 1.235 | 2.05 | 4.941 | 0.25 | 1.235 | 8.92 | 4.941
6 x CLT ép. 16 cm | 03-Toiture | FLOOR | B1020 Roof Construction (Uniformat) | CLT | 2.82 | 0.661 | 1.5 | 4.23 | 0.16 | 0.677 | 8.64 | 4.232 | yes
CLT ép. 16 cm | 03-Toiture | FLOOR | B1020 Roof Construction (Uniformat) | CLT | 1.5 | 0.306 | 1.31 | 1.965 | 0.16 | 0.314 | 5.62 | 1.966 | yes
CLT ép. 16 cm | 03-Toiture | FLOOR | B1020 Roof Construction (Uniformat) | CLT | 3.67 | 1.485 | 2.528 | 9.278 | 0.16 | 1.485 | 12.44 | 9.282 | yes
CLT ép. 16 cm | 03-Toiture | FLOOR | B1020 Roof Construction (Uniformat) | CLT | 2.82 | 0.677 | 1.5 | 4.23 | 0.16 | 0.677 | 8.64 | 4.232 | yes
CLT ép. 16 cm | 03-Toiture | FLOOR | B1020 Roof Construction (Uniformat) | CLT | 1.23 | 0.982 | 4.99 | 6.138 | 0.16 | 0.982 | 12.44 | 6.14 | yes
CLT ép. 16 cm | 03-Toiture | FLOOR | B1020 Roof Construction (Uniformat) | CLT | 1.23 | 0.722 | 3.67 | 4.514 | 0.16 | 0.722 | 9.8 | 4.516 | yes
5 x CLT ép. 16 cm | 03-Toiture | FLOOR | B1020 Roof Construction (Uniformat) | CLT | 4.99 | 2.124 | 2.66 | 13.273 | 0.16 | 2.124 | 15.3 | 13.279 | yes
7 x CLT ép. 16 cm | 03-Toiture | FLOOR | B1020 Roof Construction (Uniformat) | CLT | 2.66 | 1.562 | 3.67 | 9.762 | 0.16 | 1.562 | 12.66 | 9.766 | yes
CLT ép. 16 cm | 03-Toiture | FLOOR | B1020 Roof Construction (Uniformat) | CLT | 2.5 | 2.736 | 6.84 | 17.1 | 0.16 | 2.736 | 18.68 | 17.107 | yes
CLT ép. 16 cm | 03-Toiture | FLOOR | B1020 Roof Construction (Uniformat) | CLT | 6.84 | 2.476 | 2.262 | 15.475 | 0.16 | 2.476 | 19.04 | 15.481 | yes
CLT ép. 16 cm | 03-Toiture | FLOOR | B1020 Roof Construction (Uniformat) | CLT | 6.84 | 2.476 | 2.262 | 15.475 | 0.16 | 2.476 | 19.04 | 15.482 | yes
CLT ép. 16 cm | 03-Toiture | FLOOR | B1020 Roof Construction (Uniformat) | CLT | 6.84 | 2.736 | 2.5 | 17.1 | 0.16 | 2.736 | 18.68 | 17.108 | yes
CLT ép. 16 cm | 03-Toiture | FLOOR | B1020 Roof Construction (Uniformat) | CLT | 3.67 | 1.562 | 2.66 | 9.762 | 0.16 | 1.562 | 12.66 | 9.766 | yes
CLT ép. 16 cm | 03-Toiture | FLOOR | B1020 Roof Construction (Uniformat) | CLT | 1.5 | 0.629 | 2.63 | 3.945 | 0.16 | 0.631 | 8.26 | 3.947 | yes
CLT ép. 16 cm | 03-Toiture | FLOOR | B1020 Roof Construction (Uniformat) | CLT | 2.82 | 0 | 1.5 | 4.23 | 0 | 0 | 8.64 | 0 | yes
CLT ép. 16 cm | 03-Toiture | FLOOR | B1020 Roof Construction (Uniformat) | CLT | 4.99 | 2.338 | 3.332 | 16.627 | 0.16 | 2.66 | 16.94 | 14.619 | yes
Dalle BA R+2 | 03-Toiture | FLOOR | B1020 Roof Construction (Uniformat) | C30/37 | 4.95 | 1.947 | 2.66 | 13.167 | 0.16 | 2.107 | 15.22 | 12.173
Dalle BA R+2 | 03-Toiture | FLOOR | B1020 Roof Construction (Uniformat) | C30/37 | 1.64 | 0.278 | 1.06 | 1.738 | 0.16 | 0.278 | 5.399 | 1.739
Dalle BA R+2 | 03-Toiture | FLOOR | B1020 Roof Construction (Uniformat) | C30/37 | 5.57 | 2.38 | 2.863 | 15.948 | 0.16 | 2.552 | 21.04 | 14.955
Radier Audit. | -01-Fondations | FLOOR | A4020 Structural Slabs-on-Grade (Uniformat) | C30/37 | 15.615 | 10.386 | 2.661 | 41.545 | 0.25 | 10.386 | 36.683 | 41.545 | yes
Dalle accès Audit. | -01-Fondations | FLOOR | A4020 Structural Slabs-on-Grade (Uniformat) | C30/37 | 4.35 | 5.655 | 2 | 8.7 | 0.65 | 5.655 | 12.7 | 8.7 | yes
Radier Sas | -01-Fondations | FLOOR | A4020 Structural Slabs-on-Grade (Uniformat) | C30/37 | 9.5 | 7.624 | 3.21 | 30.495 | 0.25 | 7.624 | 25.42 | 30.495 | yes
Radier Audit. | -01-Fondations | FLOOR | A4020 Structural Slabs-on-Grade (Uniformat) | C30/37 | 20.9 | 98.406 | 18.834 | 393.624 | 0.25 | 98.406 | 77.618 | 393.623 | yes
Dalle BA 20 cm Audit. | 00-Rez | FLOOR | B1010 Floor Construction (Uniformat) | Dalle BA 20 cm | 6.4 | 4.004 | 3.128 | 20.019 | 0.2 | 4.004 | 21.792 | 20.019 | yes
Hourdis BA 16+4 | 00-Rez | FLOOR | B1010 Floor Construction (Uniformat) | Hourdis BA 16+4 | 15.768 | 11.748 | 3.725 | 58.741 | 0.2 | 11.748 | 37.688 | 58.741 | yes
Hourdis BA 16+4 | 00-Rez | FLOOR | B1010 Floor Construction (Uniformat) | Hourdis BA 16+4 | 13.846 | 12.434 | 4.49 | 62.17 | 0.2 | 12.434 | 37.28 | 62.17 | yes
Dalle BA 20 cm sas | 01-Toiture | FLOOR | B1020 Roof Construction (Uniformat) | C30/37 | 8.9 | 5.892 | 3.31 | 29.459 | 0.2 | 5.892 | 24.42 | 29.459 | yes
Dalles TT | 01-Toiture | FLOOR | B1010 Floor Construction (Uniformat) | Béton armé | 20.4 | 22.424 | 18.32 | 373.73 | 0.06 | 22.424 | 77.44 | 373.73 | yes
Hourdis BA 16+6 | 01-Toiture | FLOOR | B1020 Roof Construction (Uniformat) | Hourdis BA 16+6 | 20.081 | 19.419 | 4.486 | 90.086 | 0.22 | 19.819 | 49.772 | 88.267 | yes
Radier PosteGarde | -01-Fondations | FLOOR | A4020 Structural Slabs-on-Grade (Uniformat) | C30/37 | 3 | 4.35 | 5.8 | 17.4 | 0.25 | 4.35 | 17.6 | 17.4 | yes
Toiture PosteGarde | 00-Rez | FLOOR | B1020 Roof Construction (Uniformat) | C30/37 | 3 | 3.48 | 5.8 | 17.4 | 0.2 | 3.48 | 17.6 | 17.4
Auvent PosteGarde | 00-Rez | FLOOR | B1020 Roof Construction (Uniformat) | C30/37 | 2.01 | 2.316 | 5.76 | 11.578 | 0.2 | 2.316 | 15.54 | 11.578

# IfcStair (7)
Classification: B1080 Stairs (Uniformat); Material: C30/37
Name | In
2 x Escalier Préfab. | 00-Rez
2 x Escalier Préfab. | 01-Etage1
Escalier BA Accès Audiy. | -01-Fondations
2 x Escalier BA | 00-Rez

# IfcWall (202)
Pset_WallCommon - Status: NEW; IsExternal: yes
Name | In | Classification | Material | LoadBearing | GrossSideArea (m2) | Width (m) | NetSideArea (m2) | GrossVolume (m3) | NetVolume (m3) | Length (m) | GrossFootprintArea (m2) | Height (m)
Voiles Fosse | -01-Fondations | A2010 Walls for Subgrade Enclosure (Uniformat) | C30/37 | yes | 1.186 | 0.2 | 1.186 | 0.237 | 0.237 | 2.01 | 0.402 | 0.59
Voiles Fosse | -01-Fondations | A2010 Walls for Subgrade Enclosure (Uniformat) | C30/37 | yes | 1.091 | 0.2 | 1.091 | 0.218 | 0.218 | 1.85 | 0.37 | 0.59
Voiles Fosse | -01-Fondations | A2010 Walls for Subgrade Enclosure (Uniformat) | C30/37 | yes | 1.304 | 0.2 | 1.304 | 0.261 | 0.261 | 2.21 | 0.442 | 0.59
Voiles Fosse | -01-Fondations | A2010 Walls for Subgrade Enclosure (Uniformat) | C30/37 | yes | 1.209 | 0.2 | 1.209 | 0.242 | 0.242 | 2.05 | 0.41 | 0.59
Voile BA Axe 2.6 | 00-Rez | B2010 Exterior Walls (Uniformat) | C30/37 | yes | 10.179 | 0.2 | 8.529 | 2.036 | 1.706 | 2.9 | 0.58 | 3.51
Voile BA Axe 2.6 | 00-Rez | B2010 Exterior Walls (Uniformat) | C30/37 | yes | 20.112 | 0.2 | 16.542 | 4.023 | 3.309 | 5.73 | 1.146 | 3.51
Voile BA Esc. RDC | 00-Rez | B1010 Floor Construction (Uniformat) | C30/37 | yes | 11.618 | 0.2 | 11.618 | 2.324 | 2.324 | 3.31 | 0.662 | 3.51
Voile BA Asc. RDC | 00-Rez | B1010 Floor Construction (Uniformat) | C30/37 | yes | 5.791 | 0.2 | 5.792 | 1.158 | 1.158 | 1.65 | 0.33 | 3.51
Voile BA Esc. RDC | 00-Rez | B1010 Floor Construction (Uniformat) | C30/37 | yes | 17.374 | 0.2 | 17.375 | 3.475 | 3.475 | 4.95 | 0.99 | 3.51
2 x Voile BA Esc. RDC | 00-Rez | B1010 Floor Construction (Uniformat) | C30/37 | yes | 17.69 | 0.2 | 17.69 | 3.538 | 3.538 | 5.04 | 1.008 | 3.51
Maçonnerie Admin. | 00-Rez | B1010 Exterior Walls (Uniformat) | Silico-calcaire 15 cm | yes | 4.775 | 0.15 | 4.775 | 0.716 | 0.716 | 2.66 | 0.399 | 1.795
Maçonnerie Admin. | 00-Rez | B1010 Floor Construction (Uniformat) | Silico-calcaire 15 cm | yes | 22.168 | 0.15 | 19.502 | 3.325 | 2.925 | 6.8 | 1.02 | 3.26
Maçonnerie Admin. | 00-Rez | B1010 Floor Construction (Uniformat) | Silico-calcaire 15 cm | yes | 7.26 | 0.15 | 6.531 | 1.089 | 0.98 | 2.319 | 0.348 | 3.13
Maçonnerie Admin. | 00-Rez | B1010 Exterior Walls (Uniformat) | Silico-calcaire 15 cm | yes | 5.794 | 0.15 | 5.794 | 0.869 | 0.869 | 2.16 | 0.324 | 2.683
Maçonnerie Admin. | 00-Rez | B1010 Exterior Walls (Uniformat) | Silico-calcaire 15 cm | yes | 2.142 | 0.15 | 2.142 | 0.321 | 0.321 | 1.2 | 0.18 | 1.785
Maçonnerie Admin. | 00-Rez | B1010 Exterior Walls (Uniformat) | Silico-calcaire 15 cm | yes | 4.89 | 0.15 | 4.89 | 0.734 | 0.734 | 1.5 | 0.225 | 3.26
Maçonnerie Admin. | 00-Rez | B1010 Exterior Walls (Uniformat) | Silico-calcaire 15 cm | yes | 3.763 | 0.15 | 3.763 | 0.564 | 0.564 | 1.35 | 0.203 | 2.787
Maçonnerie Admin. | 00-Rez | B1010 Floor Construction (Uniformat) | Silico-calcaire 15 cm | yes | 8.684 | 0.15 | 8.527 | 1.303 | 1.279 | 3.53 | 0.53 | 2.46
Maçonnerie Admin. | 00-Rez | B1010 Floor Construction (Uniformat) | Silico-calcaire 15 cm | yes | 39.034 | 0.15 | 39.034 | 5.855 | 5.855 | 12.16 | 1.824 | 3.21
Maçonnerie Admin. | 00-Rez | B1010 Floor Construction (Uniformat) | Silico-calcaire 15 cm | yes | 7.262 | 0.15 | 6.533 | 1.089 | 0.98 | 2.32 | 0.348 | 3.13
Maçonnerie Admin. | 00-Rez | B1010 Floor Construction (Uniformat) | Silico-calcaire 21,4 cm | yes | 12.07 | 0.214 | 12.054 | 2.583 | 2.579 | 3.76 | 0.805 | 3.21
Maçonnerie Admin. | 00-Rez | B1010 Floor Construction (Uniformat) | Silico-calcaire 21,4 cm | yes | 10.079 | 0.214 | 8.904 | 2.157 | 1.905 | 3.22 | 0.689 | 3.13
Maçonnerie Admin. | 00-Rez | B1010 Exterior Walls (Uniformat) | Silico-calcaire 15 cm | yes | 0.574 | 0.15 | 0.574 | 0.086 | 0.086 | 0.2 | 0.03 | 2.87
Voile BA Axe 2.A | 00-Rez | B2010 Exterior Walls (Uniformat) | C30/37 | yes | 6.599 | 0.2 | 6.599 | 1.32 | 1.32 | 1.88 | 0.376 | 3.51
Voile BA Axe 2.6 | 00-Rez | B2010 Exterior Walls (Uniformat) | C30/37 | yes | 20.604 | 0.2 | 18.954 | 4.121 | 3.791 | 5.87 | 1.174 | 3.51
Voile BA Asc. R+1 | 01-Etage1 | B1010 Floor Construction (Uniformat) | C30/37 | yes | 6.216 | 0.2 | 6.216 | 1.243 | 1.243 | 1.85 | 0.37 | 3.36
Voile BA Asc. R+1 | 01-Etage1 | B1010 Floor Construction (Uniformat) | C30/37 | yes | 10.45 | 0.2 | 10.45 | 2.09 | 2.09 | 3.11 | 0.622 | 3.36
3 x Voile BA Esc. R+1 | 01-Etage1 | B1010 Floor Construction (Uniformat) | C30/37 | yes | 16.632 | 0.2 | 16.632 | 3.326 | 3.326 | 4.95 | 0.99 | 3.36
Voile BA Esc. R+1 | 01-Etage1 | B2010 Exterior Walls (Uniformat) | C30/37 | yes | 10.282 | 0.2 | 8.742 | 2.056 | 1.748 | 3.06 | 0.612 | 3.36
Voile BA Axe 2.A | 01-Etage1 | B2010 Exterior Walls (Uniformat) | C30/37 | yes | 17.304 | 0.2 | 17.304 | 3.461 | 3.461 | 5.15 | 1.03 | 3.36
Voila BA Axe 2.6 | 01-Etage1 | B2010 Exterior Walls (Uniformat) | C30/37 | yes | 15.96 | 0.2 | 14.42 | 3.192 | 2.884 | 4.75 | 0.95 | 3.36
Voile BA Esc. R+1 | 01-Etage1 | B1010 Floor Construction (Uniformat) | C30/37 | yes | 4.67 | 0.2 | 4.67 | 0.934 | 0.934 | 1.39 | 0.278 | 3.36
Panneaux CLT R+1 | 01-Etage1 | B2010 Exterior Walls (Uniformat) | CLT | yes | 12.365 | 0.16 | 12.261 | 1.978 | 1.962 | 3.68 | 0.589 | 3.36
Panneaux CLT R+1 | 01-Etage1 | B2010 Exterior Walls (Uniformat) | CLT | yes | 9.442 | 0.16 | 9.442 | 1.511 | 1.511 | 2.81 | 0.45 | 3.36
Voile BA Axe 2.A | 01-Etage1 | B2010 Exterior Walls (Uniformat) | C30/37 | yes | 0.683 | 0.16 | 0.683 | 0.109 | 0.109 | 0.61 | 0.098 | 1.12
Panneau CLT R+2 | 02-Etage2 | B2010 Exterior Walls (Uniformat) | CLT | yes | 8.065 | 0.16 | 8.065 | 1.29 | 1.29 | 2.81 | 0.45 | 2.87
Panneau CLT R+2 | 02-Etage2 | B2010 Exterior Walls (Uniformat) | CLT | yes | 10.562 | 0.16 | 10.562 | 1.69 | 1.69 | 3.68 | 0.589 | 2.87
2 x Voile BA Asc. R+2 | 02-Etage2 | B1020 Roof Construction (Uniformat) | C30/37 | yes | 8.243 | 0.2 | 8.243 | 1.649 | 1.649 | 2.21 | 0.442 | 3.73
2 x Voile BA Asc. R+2 | 02-Etage2 | B1020 Roof Construction (Uniformat) | C30/37 | yes | 2.583 | 0.2 | 2.583 | 0.517 | 0.517 | 0.9 | 0.18 | 2.87
Voile BA Asc. R+2 | 02-Etage2 | B1020 Roof Construction (Uniformat) | C30/37 | yes | 7.646 | 0.2 | 7.647 | 1.529 | 1.529 | 2.05 | 0.41 | 3.73
Voile BA Esc. R+2 | 02-Etage2 | B2010 Exterior Walls (Uniformat) | C30/37 | yes | 14.206 | 0.2 | 14.207 | 2.841 | 2.841 | 4.95 | 0.99 | 2.87
Voile BA Esc. R+2 | 02-Etage2 | B1020 Roof Construction (Uniformat) | C30/37 | yes | 4.707 | 0.2 | 4.707 | 0.941 | 0.941 | 1.64 | 0.328 | 2.87
Voile BA Esc. R+2 | 02-Etage2 | B1020 Roof Construction (Uniformat) | C30/37 | yes | 14.207 | 0.2 | 14.207 | 2.841 | 2.841 | 4.95 | 0.99 | 2.87
Voile BA Esc. R+2 | 02-Etage2 | B1020 Roof Construction (Uniformat) | C30/37 | yes | 14.206 | 0.2 | 14.207 | 2.841 | 2.841 | 4.95 | 0.99 | 2.87
Voile BA Esc. R+2 | 02-Etage2 | B2010 Exterior Walls (Uniformat) | C30/37 | yes | 8.782 | 0.2 | 7.242 | 1.756 | 1.448 | 3.06 | 0.612 | 2.87
Voile BA Axe 2.6 | 02-Etage2 | B2010 Exterior Walls (Uniformat) | C30/37 | yes | 14.207 | 0.2 | 12.667 | 2.841 | 2.533 | 4.95 | 0.99 | 2.87
Panneau CLT R+2 | 03-Toiture | B2010 Exterior Walls (Uniformat) | CLT | yes | 0.569 | 0.16 | 0.569 | 0.091 | 0.091 | 2.81 | 0.45 | 0.202
Panneau CLT R+2 | 03-Toiture | B2010 Exterior Walls (Uniformat) | CLT | yes | 0.745 | 0.16 | 0.745 | 0.119 | 0.119 | 3.68 | 0.589 | 0.202
Voile BA Axe 2.6 | 03-Toiture | B2010 Exterior Walls (Uniformat) | C30/37 | yes | 0.964 | 0.192 | 0.924 | 0.185 | 0.185 | 4.75 | 0.91 | 0.203
Voile BA Esc. R+2 | 03-Toiture | B2010 Exterior Walls (Uniformat) | C30/37 | yes | 0.581 | 0.2 | 0.581 | 0.116 | 0.116 | 2.86 | 0.572 | 0.203
2 x Voile BA Esc. R+2 | 03-Toiture | B2010 Exterior Walls (Uniformat) | C30/37 | yes | 1.428 | 0.2 | 1.428 | 0.286 | 0.286 | 5.15 | 1.03 | 0.277
Voile BA Esc. R+2 | 03-Toiture | B2010 Exterior Walls (Uniformat) | C30/37 | yes | 1.387 | 0.2 | 1.387 | 0.277 | 0.277 | 4.95 | 0.99 | 0.28
Voile BA Esc. R+2 | 03-Toiture | B2010 Exterior Walls (Uniformat) | C30/37 | yes | 0.419 | 0.2 | 0.419 | 0.084 | 0.084 | 1.84 | 0.368 | 0.228
Voile BA Asc. R+2 | 03-Toiture | B2010 Exterior Walls (Uniformat) | C30/37 | yes | 0 | 0.2 | 0.163 | 0 | -0.029 | 0.9 | 0.18 | 0
Voile BA Asc. R+2 | 03-Toiture | B2010 Exterior Walls (Uniformat) | C30/37 | yes | 0.307 | 0.2 | 0.163 | 0.061 | 0.033 | 0.9 | 0.18 | 0.341
Voile BA Axe 1.7 | 00-Rez | B2010 Exterior Walls (Uniformat) | C30/37 | yes | 80.256 | 0.25 | 77.036 | 20.064 | 19.248 | 20.9 | 5.225 | 3.84
Voile BA Axe 1.5 | 00-Rez | B2010 Exterior Walls (Uniformat) | C30/37 | yes | 105.672 | 0.2 | 97.171 | 21.134 | 19.429 | 20.4 | 4.08 | 5.18
Voile BA Axe 1.A | 00-Rez | B2010 Exterior Walls (Uniformat) | C30/37 | yes | 26.672 | 0.25 | 26.672 | 6.668 | 6.668 | 12.581 | 3.145 | 2.12
Voile BA Axe 1.A | 00-Rez | B2010 Exterior Walls (Uniformat) | C30/37 | yes | 17.265 | 0.25 | 13.18 | 4.316 | 3.295 | 4.496 | 1.124 | 3.84
Voile BA Axe 1.A | 00-Rez | B2010 Exterior Walls (Uniformat) | C30/37 | yes | 25.861 | 0.25 | 20.715 | 6.465 | 5.178 | 4.992 | 1.248 | 5.18
Voile BA Axe 1.D | 00-Rez | B2010 Exterior Walls (Uniformat) | C30/37 | yes | 0.402 | 0.25 | 0.277 | 0.101 | 0.07 | 0.078 | 0.019 | 5.18
Voile BA Axe 1.D | 00-Rez | B2010 Exterior Walls (Uniformat) | C30/37 | yes | 26.672 | 0.25 | 26.672 | 6.668 | 6.668 | 12.581 | 3.145 | 2.12
Voile BA Axe 1.D | 00-Rez | B2010 Exterior Walls (Uniformat) | C30/37 | yes | 25.86 | 0.25 | 14.461 | 6.465 | 3.615 | 4.992 | 1.248 | 5.18
Voile BA Axe 1.A | 00-Rez | B2010 Exterior Walls (Uniformat) | C30/37 | yes | 17.265 | 0.25 | 12.989 | 4.316 | 3.247 | 4.496 | 1.124 | 3.84
Voile BA Axe 1.6 | 00-Rez | B2010 Exterior Walls (Uniformat) | C30/37 | yes | 0.314 | 0.2 | 0.314 | 0.063 | 0.063 | 0.1 | 0.02 | 3.14
Voile BA Axe 1.6 | 00-Rez | B2010 Exterior Walls (Uniformat) | C30/37 | yes | 10.144 | 0.2 | 5.806 | 2.029 | 1.161 | 3.21 | 0.642 | 3.16
Voile BA Axe 1.3 | 00-Rez | B2010 Exterior Walls (Uniformat) | C30/37 | yes | 0.314 | 0.2 | 0.314 | 0.063 | 0.063 | 0.1 | 0.02 | 3.14
Voile BA Axe 1.3 | 00-Rez | B2010 Exterior Walls (Uniformat) | C30/37 | yes | 10.144 | 0.2 | 10.144 | 2.029 | 2.029 | 3.21 | 0.642 | 3.16
Voile BA Axe 1.1 | 00-Rez | B2010 Exterior Walls (Uniformat) | C30/37 | yes | 72.364 | 0.25 | 72.364 | 18.091 | 18.091 | 15.076 | 3.769 | 4.8
2 x Voile BA Axe 1.1 | 00-Rez | B2010 Exterior Walls (Uniformat) | C30/37 | yes | 4.632 | 0.25 | 4.632 | 1.158 | 1.158 | 2.662 | 0.666 | 1.74
Voile BA Axe 1.1 | 00-Rez | B2010 Exterior Walls (Uniformat) | C30/37 | no | 7.752 | 0.2 | 7.752 | 1.55 | 1.55 | 20.4 | 4.08 | 0.38
2 x Voile BA Axe 1.1 | 00-Rez | B2010 Exterior Walls (Uniformat) | C30/37 | no | 6.936 | 0.15 | 6.936 | 1.04 | 1.04 | 20.4 | 3.06 | 0.34
Voile BA oblique Axe 1.D | 00-Rez | B2010 Exterior Walls (Uniformat) | C30/37 | yes | 59.036 | 0.25 | 38.426 | 14.759 | 9.606 | 13.237 | 3.309 | 4.46
Maçonnerie Audit. | 00-Rez | C1010 Interior Partitions (Uniformat) | Silico-calcaire 15 cm | no | 20.288 | 0.15 | 17.908 | 3.043 | 2.686 | 6.4 | 0.96 | 3.17
Maçonnerie Audit. | 00-Rez | C1010 Interior Partitions (Uniformat) | Silico-calcaire 15 cm | no | 9.502 | 0.15 | 9.502 | 1.425 | 1.425 | 3.21 | 0.481 | 2.96
6 x Maçonnerie Audit. | 00-Rez | B1010 Floor Construction (Uniformat) | Silico-calcaire 15 cm | yes | 0.11 | 0.15 | 0.11 | 0.016 | 0.016 | 1 | 0.15 | 0.11
6 x Maçonnerie Audit. | 00-Rez | B1010 Floor Construction (Uniformat) | Silico-calcaire 15 cm | yes | 0.26 | 0.15 | 0.26 | 0.039 | 0.039 | 1 | 0.15 | 0.26
6 x Maçonnerie Audit. | 00-Rez | B1010 Floor Construction (Uniformat) | Silico-calcaire 15 cm | yes | 0.41 | 0.15 | 0.41 | 0.061 | 0.061 | 1 | 0.15 | 0.41
6 x Maçonnerie Audit. | 00-Rez | B1010 Floor Construction (Uniformat) | Silico-calcaire 15 cm | yes | 0.56 | 0.15 | 0.56 | 0.084 | 0.084 | 1 | 0.15 | 0.56
6 x Maçonnerie Audit. | 00-Rez | B1010 Floor Construction (Uniformat) | Silico-calcaire 15 cm | yes | 0.71 | 0.15 | 0.71 | 0.106 | 0.106 | 1 | 0.15 | 0.71
Maçonnerie Audit. | 00-Rez | B1010 Floor Construction (Uniformat) | Silico-calcaire 15 cm | yes | 1.971 | 0.15 | 1.971 | 0.296 | 0.296 | 1.101 | 0.165 | 1.79
Maçonnerie Audit. | 00-Rez | B1010 Floor Construction (Uniformat) | Silico-calcaire 15 cm | yes | 1.52 | 0.15 | 1.52 | 0.228 | 0.228 | 1 | 0.15 | 1.52
2 x Maçonnerie Audit. | 00-Rez | B1010 Floor Construction (Uniformat) | Silico-calcaire 15 cm | yes | 1.25 | 0.15 | 1.25 | 0.187 | 0.187 | 1 | 0.15 | 1.25
2 x Maçonnerie Audit. | 00-Rez | B1010 Floor Construction (Uniformat) | Silico-calcaire 15 cm | yes | 0.98 | 0.15 | 0.98 | 0.147 | 0.147 | 1 | 0.15 | 0.98
4 x Maçonnerie Audit. | 00-Rez | B1010 Floor Construction (Uniformat) | Silico-calcaire 15 cm | yes | 0.845 | 0.15 | 0.845 | 0.127 | 0.127 | 1 | 0.15 | 0.845
4 x Maçonnerie Audit. | 00-Rez | B1010 Floor Construction (Uniformat) | Silico-calcaire 15 cm | yes | 1.385 | 0.15 | 1.385 | 0.208 | 0.208 | 1 | 0.15 | 1.385
4 x Maçonnerie Audit. | 00-Rez | B1010 Floor Construction (Uniformat) | Silico-calcaire 15 cm | yes | 1.115 | 0.15 | 1.115 | 0.167 | 0.167 | 1 | 0.15 | 1.115
4 x Maçonnerie Audit. | 00-Rez | B1010 Floor Construction (Uniformat) | Silico-calcaire 15 cm | yes | 1.788 | 0.15 | 1.788 | 0.268 | 0.268 | 1.08 | 0.162 | 1.655
Maçonnerie Audit. | 00-Rez | B1010 Floor Construction (Uniformat) | Silico-calcaire 15 cm | yes | 3.194 | 0.15 | 3.194 | 0.479 | 0.479 | 2.101 | 0.315 | 1.52
Maçonnerie Audit. | 00-Rez | B1010 Floor Construction (Uniformat) | Silico-calcaire 15 cm | yes | 0.119 | 0.15 | 0.119 | 0.018 | 0.018 | 1.082 | 0.162 | 0.11
Maçonnerie Audit. | 00-Rez | B1010 Floor Construction (Uniformat) | Silico-calcaire 15 cm | yes | 2.346 | 0.15 | 1.446 | 0.352 | 0.217 | 4.6 | 0.69 | 0.51
Maçonnerie Audit. | 00-Rez | B1010 Floor Construction (Uniformat) | Silico-calcaire 15 cm | yes | 4.386 | 0.15 | 4.386 | 0.658 | 0.658 | 7.975 | 1.196 | 0.55
Maçonnerie Audit. | 00-Rez | B1010 Floor Construction (Uniformat) | Silico-calcaire 15 cm | yes | 0.784 | 0.15 | 0.784 | 0.118 | 0.118 | 1.425 | 0.214 | 0.55
Maçonnerie Audit. | 00-Rez | C1010 Interior Partitions (Uniformat) | Silico-calcaire 15 cm | no | 0.684 | 0.15 | 0.684 | 0.103 | 0.103 | 0.168 | 0.025 | 4.06
Maçonnerie Audit. | 00-Rez | B1010 Floor Construction (Uniformat) | Silico-calcaire 15 cm | yes | 0.495 | 0.15 | 0.495 | 0.074 | 0.074 | 0.9 | 0.135 | 0.55
Maçonnerie Audit. | 00-Rez | B1010 Floor Construction (Uniformat) | Silico-calcaire 15 cm | yes | 1.322 | 0.15 | 0.962 | 0.198 | 0.144 | 2.591 | 0.389 | 0.51
Maçonnerie Audit. | 00-Rez | B1010 Floor Construction (Uniformat) | Silico-calcaire 15 cm | yes | 4.06 | 0.15 | 2.62 | 0.609 | 0.393 | 7.96 | 1.194 | 0.51
Maçonnerie Audit. | 00-Rez | B1010 Floor Construction (Uniformat) | Silico-calcaire 15 cm | yes | 2.686 | 0.15 | 2.685 | 0.403 | 0.403 | 4.884 | 0.733 | 0.55
Maçonnerie Audit. | 00-Rez | B1010 Floor Construction (Uniformat) | Silico-calcaire 15 cm | yes | 0.996 | 0.15 | 0.772 | 0.149 | 0.116 | 1.402 | 0.21 | 0.71
Maçonnerie Audit. | 00-Rez | B1010 Floor Construction (Uniformat) | Silico-calcaire 15 cm | yes | 2.346 | 0.15 | 1.434 | 0.352 | 0.215 | 4.6 | 0.69 | 0.51
Maçonnerie Audit. | 00-Rez | B1010 Floor Construction (Uniformat) | Silico-calcaire 15 cm | yes | 7.7 | 0.15 | 7.7 | 1.155 | 1.155 | 14 | 2.1 | 0.55
Maçonnerie Audit. | 00-Rez | B1010 Floor Construction (Uniformat) | Silico-calcaire 15 cm | yes | 1.467 | 0.15 | 1.107 | 0.22 | 0.166 | 2.877 | 0.432 | 0.51
Maçonnerie Audit. | 00-Rez | B1010 Floor Construction (Uniformat) | Silico-calcaire 15 cm | yes | 0.639 | 0.15 | 0.495 | 0.096 | 0.074 | 0.9 | 0.135 | 0.71
Maçonnerie Audit. | 00-Rez | B1010 Floor Construction (Uniformat) | Silico-calcaire 15 cm | yes | 2.744 | 0.15 | 2.744 | 0.412 | 0.412 | 4.989 | 0.748 | 0.55
Maçonnerie Audit. | 00-Rez | B1010 Floor Construction (Uniformat) | Silico-calcaire 15 cm | yes | 0.771 | 0.15 | 0.771 | 0.116 | 0.116 | 1.401 | 0.21 | 0.55
Maçonnerie Audit. | 00-Rez | B1010 Floor Construction (Uniformat) | Silico-calcaire 15 cm | yes | 0.712 | 0.15 | 0.712 | 0.107 | 0.107 | 2.846 | 0.427 | 0.25
Maçonnerie Audit. | 00-Rez | B1010 Floor Construction (Uniformat) | Silico-calcaire 15 cm | yes | 1.342 | 0.15 | 1.342 | 0.201 | 0.201 | 5.37 | 0.805 | 0.25
Maçonnerie Audit. | 00-Rez | C1010 Interior Partitions (Uniformat) | Silico-calcaire 15 cm | no | 0.294 | 0.15 | 0.294 | 0.044 | 0.044 | 0.1 | 0.015 | 2.94
Maçonnerie Audit. | 00-Rez | C1010 Interior Partitions (Uniformat) | Silico-calcaire 15 cm | yes | 0.294 | 0.15 | 0.294 | 0.044 | 0.044 | 0.1 | 0.015 | 2.94
Maçonnerie Audit. | 00-Rez | B1010 Floor Construction (Uniformat) | Silico-calcaire 15 cm | yes | 0.119 | 0.165 | 0.119 | 0.02 | 0.02 | 1.082 | 0.178 | 0.11
Maçonnerie Audit. | 00-Rez | B1010 Floor Construction (Uniformat) | Silico-calcaire 15 cm | yes | 0.284 | 0.164 | 0.284 | 0.047 | 0.047 | 1.093 | 0.179 | 0.26
2 x Maçonnerie Audit. | 00-Rez | B1010 Floor Construction (Uniformat) | Silico-calcaire 15 cm | yes | 0.448 | 0.164 | 0.448 | 0.073 | 0.073 | 1.093 | 0.179 | 0.41
Maçonnerie Audit. | 00-Rez | B1010 Floor Construction (Uniformat) | Silico-calcaire 15 cm | yes | 0.612 | 0.163 | 0.612 | 0.1 | 0.1 | 1.093 | 0.178 | 0.56
2 x Maçonnerie Audit. | 00-Rez | B1010 Floor Construction (Uniformat) | Silico-calcaire 15 cm | yes | 0.776 | 0.163 | 0.776 | 0.126 | 0.126 | 1.093 | 0.178 | 0.71
2 x Maçonnerie Audit. | 00-Rez | B1010 Floor Construction (Uniformat) | Silico-calcaire 15 cm | yes | 1.071 | 0.162 | 1.071 | 0.174 | 0.174 | 1.093 | 0.177 | 0.98
Maçonnerie Audit. | 00-Rez | B1010 Floor Construction (Uniformat) | Silico-calcaire 15 cm | yes | 4.798 | 0.156 | 4.8 | 0.746 | 0.746 | 3.156 | 0.491 | 1.52
Maçonnerie Audit. | 00-Rez | B1010 Floor Construction (Uniformat) | Silico-calcaire 15 cm | yes | 1.366 | 0.161 | 1.366 | 0.221 | 0.221 | 1.093 | 0.176 | 1.25
Maçonnerie Audit. | 00-Rez | B1010 Floor Construction (Uniformat) | Silico-calcaire 15 cm | yes | 0.299 | 0.149 | 0.283 | 0.045 | 0.045 | 1.15 | 0.172 | 0.26
Maçonnerie Audit. | 00-Rez | B1010 Floor Construction (Uniformat) | Silico-calcaire 15 cm | yes | 0.612 | 0.163 | 0.612 | 0.1 | 0.1 | 1.093 | 0.179 | 0.56
Maçonnerie Audit. | 00-Rez | B1010 Floor Construction (Uniformat) | Silico-calcaire 15 cm | yes | 1.451 | 0.147 | 1.37 | 0.213 | 0.213 | 1.161 | 0.171 | 1.25
Maçonnerie Audit. | 00-Rez | B1010 Floor Construction (Uniformat) | Silico-calcaire 15 cm | yes | 3.694 | 0.155 | 3.696 | 0.574 | 0.574 | 2.064 | 0.321 | 1.79
Maçonnerie Audit. | 00-Rez | B1010 Floor Construction (Uniformat) | Silico-calcaire 15 cm | yes | 1.656 | 0.156 | 1.657 | 0.258 | 0.258 | 1.09 | 0.17 | 1.52
Maçonnerie Audit. | 00-Rez | C1010 Interior Partitions (Uniformat) | Silico-calcaire 21,4 cm | yes | 0.294 | 0.214 | 0.294 | 0.063 | 0.063 | 0.1 | 0.021 | 2.94
Voile BA Axe 1.A | 00-Rez | B2010 Exterior Walls (Uniformat) | C30/37 | yes | 0.402 | 0.25 | 0.263 | 0.101 | 0.071 | 0.078 | 0.019 | 5.18
2 x Voile BA Axe 1.A | 00-Rez | B2010 Exterior Walls (Uniformat) | C30/37 | yes | 0.185 | 0.25 | 0.185 | 0.046 | 0.046 | 0.5 | 0.125 | 0.37
Voile BA Axe 1.D | 00-Rez | B2010 Exterior Walls (Uniformat) | C30/37 | yes | 0.801 | 0.122 | 0.401 | 0.098 | 0.098 | 1.145 | 0.14 | 0.7
Voile BA Axe 1.A | 00-Rez | B2010 Exterior Walls (Uniformat) | C30/37 | yes | 0.801 | 0.122 | 0.401 | 0.098 | 0.098 | 1.145 | 0.14 | 0.7
Voile BA oblique Axe 1.A | 00-Rez | B2010 Exterior Walls (Uniformat) | C30/37 | yes | 59.032 | 0.25 | 43.527 | 14.758 | 10.882 | 13.236 | 3.309 | 4.46
Voile BA Axe 1.D | 00-Rez | B2010 Exterior Walls (Uniformat) | C30/37 | yes | 2.26 | 0.25 | 1.727 | 0.565 | 0.432 | 0.5 | 0.125 | 4.52
Voile BA Axe 1.A | 00-Rez | B2010 Exterior Walls (Uniformat) | C30/37 | yes | 2.26 | 0.25 | 1.356 | 0.565 | 0.339 | 0.5 | 0.125 | 4.52
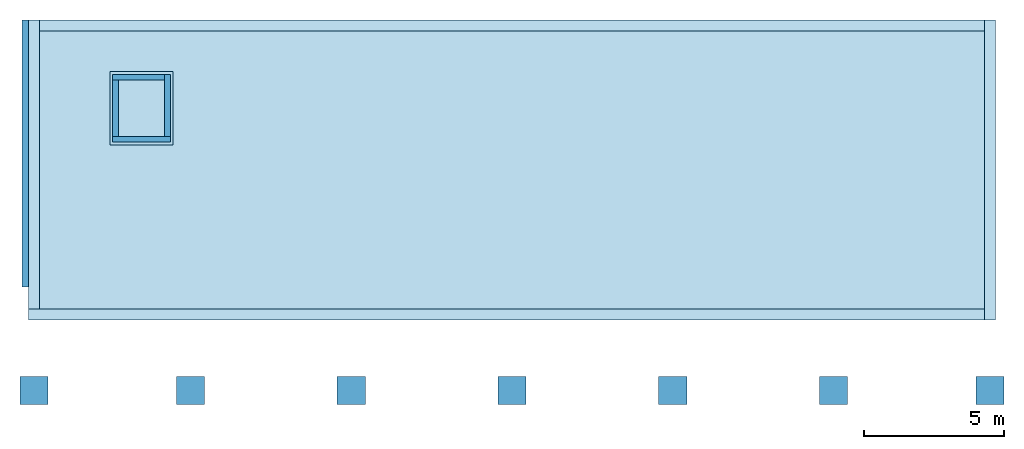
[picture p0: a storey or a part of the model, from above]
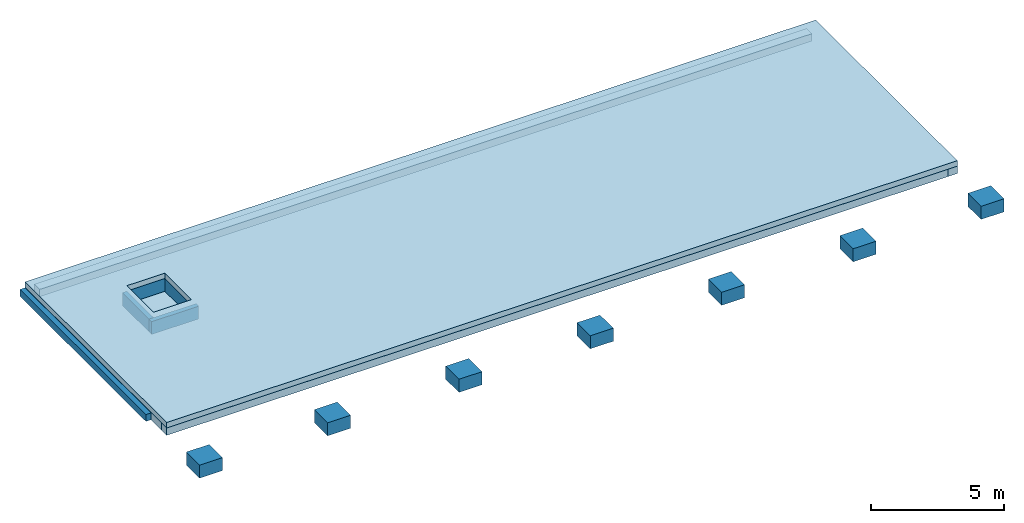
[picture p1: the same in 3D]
Properties of the parts of a building model (IFC4), part 2 of 2

# IfcWall (202)
Name | In | Classification | Material | LoadBearing | GrossSideArea (m2) | Width (m) | NetSideArea (m2) | GrossVolume (m3) | NetVolume (m3) | Length (m) | GrossFootprintArea (m2) | Height (m)
Maçonnerie Audit. | 00-Rez | C1010 Interior Partitions (Uniformat) | Silico-calcaire 21,4 cm | no | 9.502 | 0.2 | 9.502 | 1.9 | 1.9 | 3.21 | 0.642 | 2.96
Maçonnerie Audit. | 00-Rez | C1010 Interior Partitions (Uniformat) | Silico-calcaire 15 cm | no | 9.502 | 0.14 | 9.502 | 1.33 | 1.33 | 3.21 | 0.449 | 2.96
Maçonnerie Audit. | 00-Rez | C1010 Interior Partitions (Uniformat) | Silico-calcaire 15 cm | no | 16.029 | 0.19 | 15.976 | 3.045 | 3.035 | 3.168 | 0.602 | 5.06
Maçonnerie Audit. | 00-Rez | C1010 Interior Partitions (Uniformat) | Silico-calcaire 15 cm | no | 10.898 | 0.19 | 6.652 | 2.071 | 1.264 | 2.154 | 0.409 | 5.06
Maçonnerie Audit. | 00-Rez | C1010 Interior Partitions (Uniformat) | Silico-calcaire 15 cm | no | 15.535 | 0.19 | 12.792 | 2.952 | 2.431 | 3.07 | 0.583 | 5.06
Maçonnerie Audit. | 00-Rez | C1010 Interior Partitions (Uniformat) | Silico-calcaire 15 cm | no | 10.112 | 0.19 | 5.898 | 1.921 | 1.117 | 1.998 | 0.38 | 5.06
Maçonnerie Audit. | 00-Rez | C1010 Interior Partitions (Uniformat) | Silico-calcaire 15 cm | no | 12.427 | 0.15 | 12.427 | 1.864 | 1.864 | 4.33 | 0.649 | 2.87
Maçonnerie Audit. | 00-Rez | C1010 Interior Partitions (Uniformat) | Silico-calcaire 15 cm | no | 12.886 | 0.15 | 10.404 | 1.933 | 1.561 | 4.49 | 0.673 | 2.87
Acrotère Axe 1.7 | 01-Toiture | B2010 Exterior Walls (Uniformat) | C30/37 | yes | 3.641 | 0.2 | 3.641 | 0.728 | 0.728 | 3.31 | 0.662 | 1.1
Acrotère Axe 1.3 | 01-Toiture | B2010 Exterior Walls (Uniformat) | C30/37 | yes | 3.641 | 0.2 | 3.641 | 0.728 | 0.728 | 3.31 | 0.662 | 1.1
Acrotère Axe 1.7 | 01-Toiture | B2010 Exterior Walls (Uniformat) | C30/37 | yes | 35.948 | 0.25 | 35.948 | 8.987 | 8.987 | 20.9 | 5.225 | 1.72
Acrotère Axe 1.1 | 01-Toiture | B2010 Exterior Walls (Uniformat) | C30/37 | yes | 7.942 | 0.25 | 7.942 | 1.985 | 1.985 | 20.9 | 5.225 | 0.38
Acrotère Axe 1.D | 01-Toiture | B2010 Exterior Walls (Uniformat) | C30/37 | yes | 7.019 | 0.25 | 7.019 | 1.755 | 1.755 | 18.47 | 4.618 | 0.38
Acrotère Axe 1.A | 01-Toiture | B2010 Exterior Walls (Uniformat) | C30/37 | yes | 7.019 | 0.25 | 7.019 | 1.755 | 1.755 | 18.47 | 4.618 | 0.38
Acrotère Axe 1.5 | 01-Toiture | B2010 Exterior Walls (Uniformat) | C30/37 | yes | 7.752 | 0.2 | 7.752 | 1.55 | 1.55 | 20.4 | 4.08 | 0.38
Acrotère Axe 1.D | 01-Toiture | B2010 Exterior Walls (Uniformat) | C30/37 | yes | 7.716 | 0.25 | 7.716 | 1.929 | 1.929 | 4.486 | 1.122 | 1.72
Acrotère Axe 1.A | 01-Toiture | B2010 Exterior Walls (Uniformat) | C30/37 | yes | 7.716 | 0.25 | 7.716 | 1.929 | 1.929 | 4.486 | 1.122 | 1.72
2 x Voile BA PosteGarde | 00-Rez | B1010 Floor Construction (Uniformat) | C30/37 | yes | 7.176 | 0.2 | 7.176 | 1.435 | 1.435 | 2.6 | 0.52 | 2.76
Voile BA PosteGarde | 00-Rez | B1010 Floor Construction (Uniformat) | C30/37 | yes | 16.008 | 0.2 | 16.008 | 3.202 | 3.202 | 5.8 | 1.16 | 2.76
Voile BA PosteGarde | 00-Rez | B1010 Floor Construction (Uniformat) | C30/37 | yes | 16.008 | 0.2 | 10.709 | 3.202 | 2.142 | 5.8 | 1.16 | 2.76
